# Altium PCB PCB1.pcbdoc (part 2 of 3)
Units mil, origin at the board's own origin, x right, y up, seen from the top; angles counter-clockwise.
Board outline 3855 x 3785 mil, 2 copper layers (Top Layer, Bottom Layer); 109 components, 98 nets, 407 pads, 573 vias.

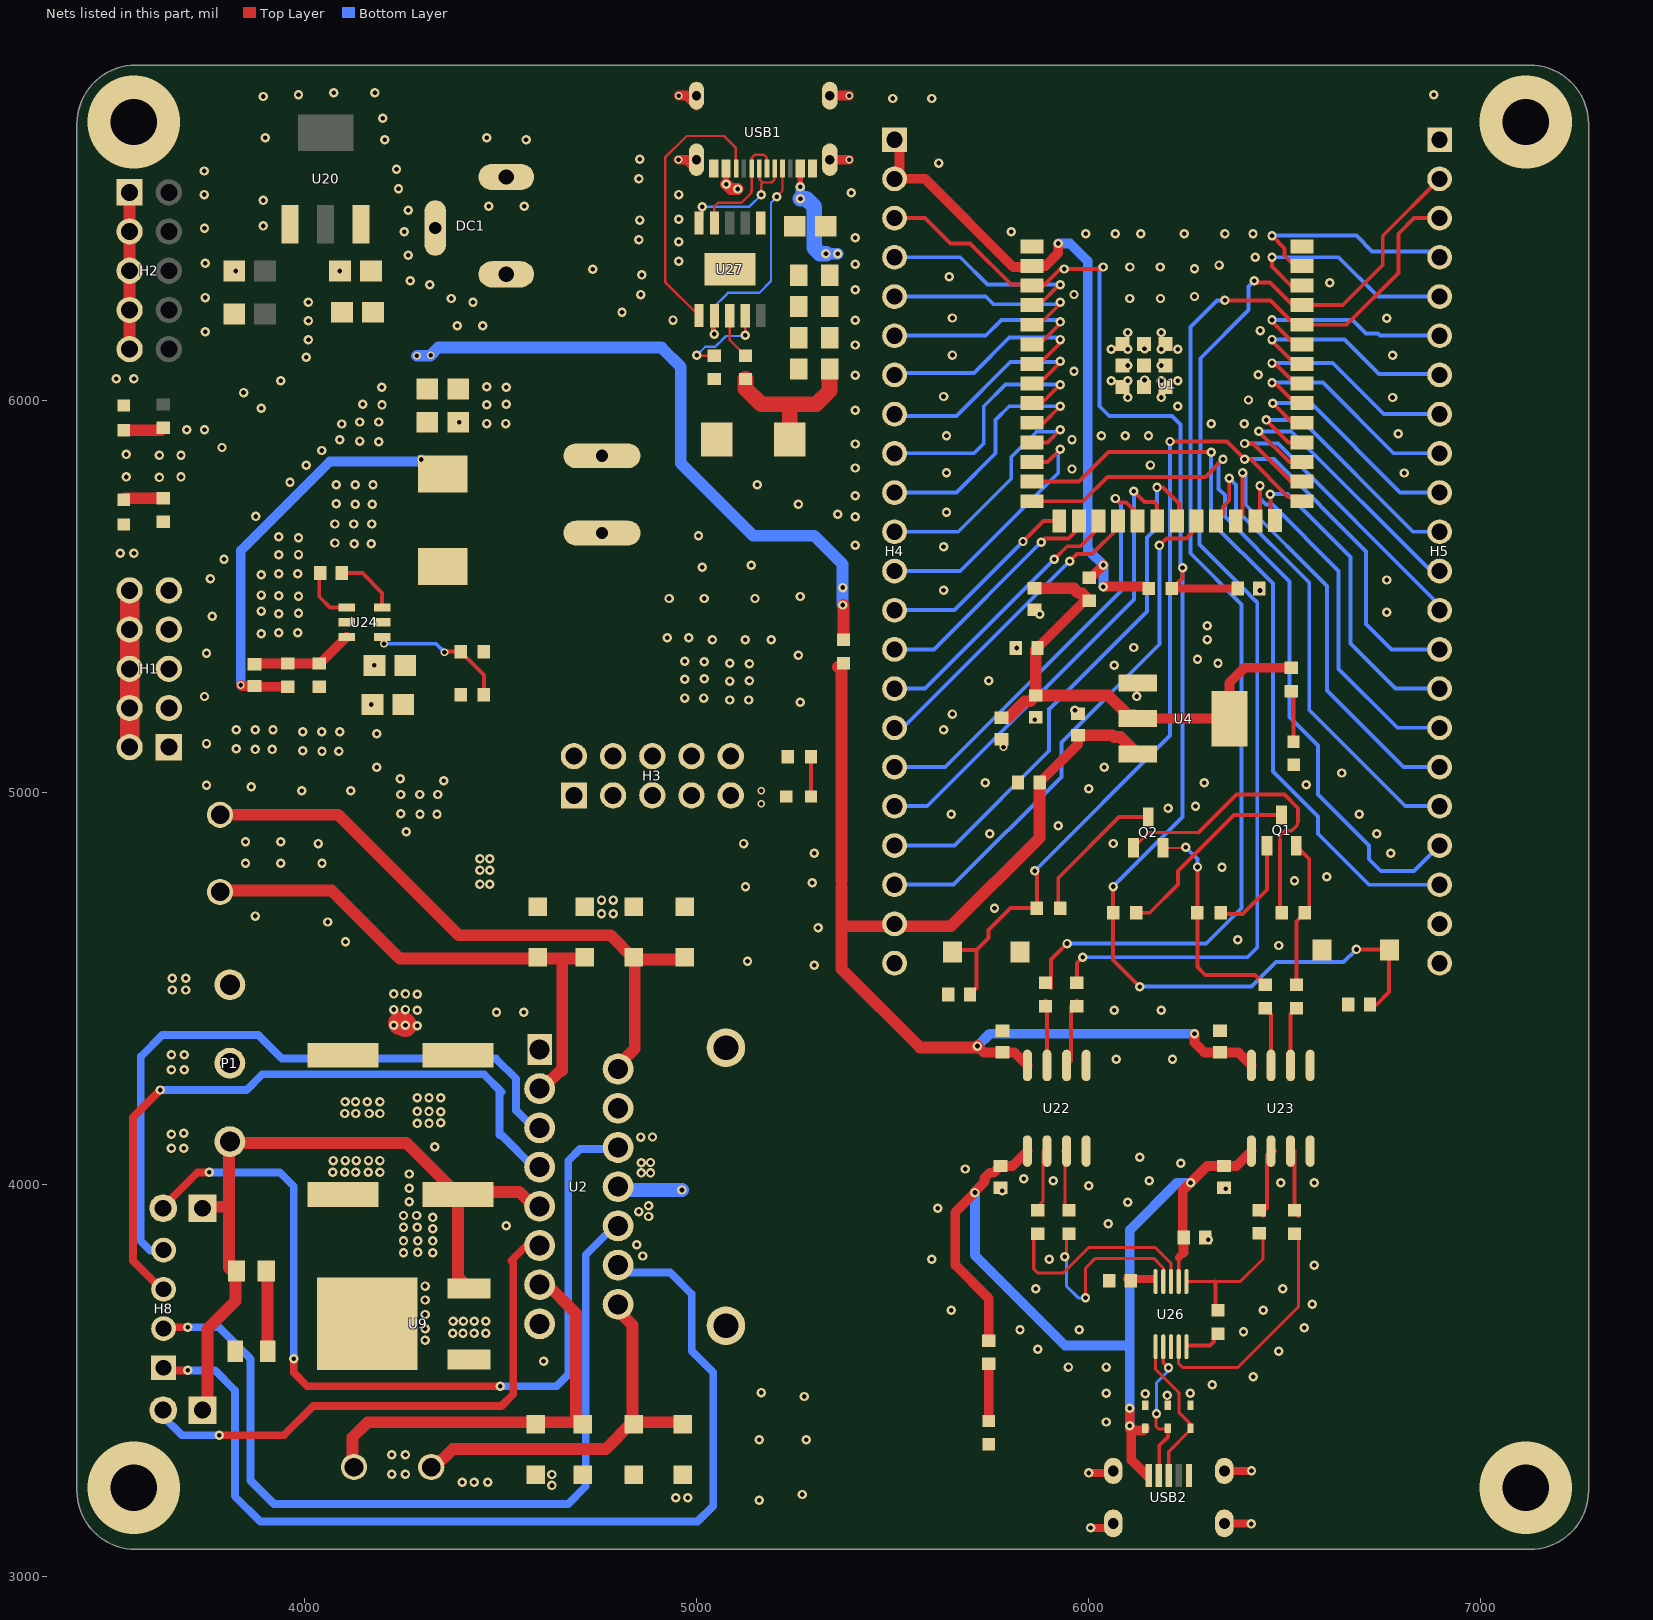
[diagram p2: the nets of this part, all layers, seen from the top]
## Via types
v1: diameter 24, hole 11.81, Top Layer to Bottom Layer, 257 vias
v2: diameter 24.02, hole 12.01, Top Layer to Bottom Layer, 174 vias
v3: diameter 24, hole 12, Top Layer to Bottom Layer, 122 vias
v4: diameter 19.68, hole 11.81, Top Layer to Bottom Layer, 16 vias
v5: diameter 236.22, hole 118.11, Top Layer to Bottom Layer, 4 vias

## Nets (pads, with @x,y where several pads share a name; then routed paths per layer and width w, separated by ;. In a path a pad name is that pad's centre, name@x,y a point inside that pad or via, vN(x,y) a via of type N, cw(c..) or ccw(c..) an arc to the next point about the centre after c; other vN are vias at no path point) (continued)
12V: C3.1 C18.2 C26.2 D1.1 D3.1 D4.1 D9.1 H3.2 H3.4 H3.6 H3.8 H3.10 P1.3 R8C1.2 R16.2 SW1C1.1 U2.4 U9.1 U24.5 | length 17.1
  Top Layer w60: 4242.77,4411.58 4252.77,4411.58 v2(4257.77,4406.58)
  other v2: 4432.77,3620.93 4378.76,3621.58 4404.54,3621.58 4462.77,3621.58 4379.3,3651.58 4405.62,3651.58 4433.01,3651.58 4462.77,3651.58 4287.77,4156.25 4317.77,4156.25 4347.77,4157.86 4347.77,4186.33 4287.77,4186.87 4317.77,4186.87 4287.77,4221.58 4317.77,4221.58 4347.77,4221.58 4288.13,4405.51 4227.77,4406.58 4288.13,4445.26 4227.77,4446.58 4257.77,4446.58 4288.13,4485.68 4227.77,4486.58 4257.77,4486.58 4447.77,4766.58 4472.77,4766.58 4447.77,4801.58 4472.77,4801.58 4447.77,4831.58 4472.77,4831.58
  other v3: 4402.77,3240.93 4432.77,3240.93 4467.77,3240.93
$1N34: D2C.2 R7C.2 | length 102.8
  Top Layer w30: D2C.2@3539.24,5746.49 3543.13,5750.39 R7C.2@3640.45,5750.39
$1N35: D3C.2 R8C.1 | length 94.8
  Top Layer w30: D3C.2@3539.51,5924.25 R8C.1@3634.34,5924.25
$1N5073: C17.2 L1.1 U24.6 | length 160.9
  Top Layer w10: C17.2@4095.59,5559.45 4148.03,5559.45 4198.27,5509.21 U24.6@4198.27,5471.85
$1N5109: C17.1 U24.1 | length 142.2
  Top Layer w10: C17.1@4040.47,5559.45 4038.03,5557.01 4038.03,5499.45 4065.63,5471.85 U24.1@4107.79,5471.85
$1N5190: R16.1 R17.2 U24.4 | length 358.9
  Top Layer w10: U24.4@4198.27,5397.05 4203.03,5392.29 v4(4203.03,5379.45) ; v4(4357.38,5358.11) 4358.72,5359.45 R17.2@4398.37,5359.45 4457.69,5300.13 R16.1@4457.69,5249.45
  Bottom Layer w10: v4(4203.03,5379.45) 4336.03,5379.45 v4(4357.38,5358.11)
$1N5474: C21.2 R18.2 R19.2 U24.3 | length 263.8
  Top Layer w25: C21.2@3873.03,5327.01 3875.13,5329.11 R18.2@3958.03,5329.11 R19.2@4038.03,5329.11 4039.85,5329.11 U24.3@4107.79,5397.05
$1N7060: R3.1 U27.9 | length 239.3
  Top Layer w6: v3(5000.89,6115.57) 5002.53,6113.93 R3.1@5045.01,6113.93 ; v3(5124.38,6166.33) U27.9@5124.38,6216.16
  Bottom Layer w6: v3(5000.89,6115.57) 5022.09,6136.77 5047.51,6136.77 5055.01,6144.27 5055.37,6144.27 5070.01,6158.92 5070.01,6159.27 5075.01,6164.27 5122.32,6164.27 v3(5124.38,6166.33)
$1N7101: R2.1 U27.8 | length 118.8
  Top Layer w6: U27.8@5085.01,6216.16 5085.01,6153.93 R2.1@5125.01,6113.93
$1N7262: C1.2 R5.2 R6.2 R7.2 R20.2 U27.1
$1N10307: D3C1.2 R8C1.1 | length 96.3
  Top Layer w10: D3C1.2@5292,4995.22 R8C1.1@5292,5091.53
$3N78: Q1.1 R10A.2 | length 256.9
  Top Layer w10: R10A.2@6336.64,4693.54 6339.95,4690.24 6392.58,4690.24 6454.58,4752.23 Q1.1@6454.58,4864.17
$3N79: Q2.1 R12A.2 | length 789.4
  Top Layer w8: Q2.1@6114.58,4859.17 6153.71,4898.31 6280.65,4898.31 ; 6487.58,4878.92 6487.58,4890.24 6500.13,4902.78 6517.58,4902.78 6533.01,4918.21 6533.01,4925.24 6533.9,4925.24 6534.42,4925.76
  Top Layer w10: 6280.65,4898.31 6377.58,4995.24 6499.26,4995.24 6534.42,4960.07 6534.42,4925.76 ; 6487.58,4878.92 6487.58,4698.28 R12A.2@6492.32,4693.54
$3N94: LED1.2 R11A.2 | length 129.4
  Top Layer w10: R11A.2@6516.98,5258.88 6522.44,5253.42 LED1.2@6522.44,5131.71
$3N145: Q2.3 R13.1 | length 373
  Top Layer w10: R13.1@5927.24,4705.24 5922.58,4709.9 5922.58,4782.58 6077.91,4937.91 Q2.3@6151.98,4937.91
$3N147: Q1.3 R8.1 | length 494.1
  Top Layer w10: R8.1@6121.64,4693.54 6155.89,4693.54 6227.58,4765.24 6227.58,4800.24 6370.26,4942.91 Q1.3@6491.98,4942.91
$3N10374: R25.1 U22.6 | length 177
  Top Layer w10: U22.6@5943.8,4304.15 5955,4315.35 5955,4455.34 R25.1@5970,4470.34
$3N10376: R7A1.1 U22.7 | length 167.8
  Top Layer w10: R7A1.1@5890,4470.34 5893.8,4466.54 U22.7@5893.8,4304.15
$3N10605: LED3.2 R2B1.1 | length 143.9
  Top Layer w25: LED3.2@5745.19,3399.29 5745.33,3399.42 R2B1.1@5745.33,3543.15
$3N10884: C16.2 U26.10 | length 66.1
  Top Layer w20: C16.2@6097.56,3760 6163.7,3760
$3N11013: R24.2 U22.3 | length 153.8
  Top Layer w8: U22.3@5933.8,4085.85 5940,4079.65 R24.2@5940,3934.66
$3N11016: R24.1 U26.9 | length 535.9
  Top Layer w8: v3(5939.36,3816.13) 5943.34,3820.11 R24.1@5943.34,3883.68 ; v3(5992.04,3711.39) 5992.04,3787.04 6017.27,3812.27 6165.75,3812.27 6190.49,3787.53 6190.49,3753.24 U26.9@6190.32,3753.07
  Bottom Layer w8: v3(5939.36,3816.13) 5943.56,3811.92 5943.56,3741.44 5973.61,3711.39 v3(5992.04,3711.39)
$3N11079: R22.2 U22.2 | length 161
  Top Layer w8: R22.2@5860,3934.66 5883.8,3958.46 U22.2@5883.8,4085.85
$3N11082: R22.1 U26.8 | length 534.9
  Top Layer w8: R22.1@5860,3875.34 5860,3785 5870,3775 5935,3775 6000,3840 6170,3840 6210,3800 U26.8@6210,3753.07
$3N11238: R26.1 U23.7 | length 152.4
  Top Layer w10: R26.1@6450,4450.34 6465,4435.34 U23.7@6465,4304.15
$3N11271: R27.1 U23.6 | length 152.4
  Top Layer w10: U23.6@6515,4304.15 6515,4435.34 R27.1@6530,4450.34
$3N11307: R28.2 U23.2 | length 184.3
  Top Layer w10: R28.2@6444.66,3920 6444.66,3930 6455,3940.34 6455,4075.85 U23.2@6465,4085.85 U23.2@6475,4085.85
$3N11312: R4.2 R28.1 U26.6 | length 343.9
  Top Layer w8: U26.6@6249.37,3753.07 6323.15,3753.07 6387.05,3753.07 6444.66,3810.68 R28.1@6444.66,3860.68
  Top Layer w10: R4.2@6320,3679.66 6323.15,3682.81 6323.15,3753.07
$3N11345: R29.2 U23.3 | length 170.3
  Top Layer w10: U23.3@6525,4085.85 6525,3929.66 R29.2@6535,3919.66
$3N11350: R29.1 U26.4 | length 588.5
  Top Layer w8: U26.4@6229.69,3586.93 6229.51,3586.75 6229.51,3543.99 6239.34,3534.16 6380.84,3534.16 6535,3688.31 R29.1@6535,3860.34
$3N15257: R4.1 U26.5 | length 95.9
  Top Layer w10: U26.5@6250.2,3586.1 6254.1,3590 6310,3590 6320,3600 R4.1@6320,3620.34
$5N2079: LED2.1 R1.1 | length 197.2
  Top Layer w30: R1.1@3900.81,3771.58 3906.07,3766.32 LED2.1@3906.07,3576.58
$5N2106: D4.2 D8.1 U2.14 U10.2 | length 1003.5
  Top Layer w30: U10.2@4323.52,3281.58 4334.17,3281.58 4378.52,3325.93 4768.36,3325.93 D4.2@4836.66,3394.23 ; U2.14@4787.77,3691.58 4836.66,3642.69 D4.2@4836.66,3394.23 ; D8.1@4962.77,3394.23 D4.2@4836.66,3394.23
$5N2107: D3.2 D7.1 U2.13 U10.1 | length 1087.1
  Top Layer w30: U10.1@4126.67,3281.58 4122.77,3285.48 4122.77,3355.93 4161.07,3394.23 D3.2@4709.07,3394.23 ; U2.13@4600,3745 4620,3745 4692.5,3672.5 4692.5,3410.8 D3.2@4709.07,3394.23 ; D3.2@4710,3393.3 D3.2@4709.07,3394.23
$5N2113: D6.1 D9.2 U2.3 U3.2 | length 1371.9
  Top Layer w30: U3.2@3785,4746.58 3788.43,4750 4070,4750 4243.3,4576.7 D6.1@4715,4576.7 ; U2.3@4587.77,4241.58 4603.42,4241.58 4652.77,4290.93 ; 4652.77,4574.07 4652.88,4574.18 ; 4657.77,4290.93 4657.77,4574.07
$5N2114: D1.2 D5.1 U2.2 U3.1 | length 1641.1
  Top Layer w30: U3.1@3785,4943.43 4086.67,4943.43 4394.17,4635.93 4781.02,4635.93 D5.1@4842.77,4574.18 ; U2.2@4787.77,4291.58 4842.77,4346.58 D5.1@4842.77,4574.18 ; D1.2@4967.77,4574.18 D5.1@4842.77,4574.18
+5V: C2.1 H6.1 H7.1 P1.1 R1.2 U2.9 U9.3 | length 1903.7
  Top Layer w30: H6.1@3737.77,3421.58 3752.77,3436.58 3752.77,3631.58 3824.73,3703.54 3824.73,3771.58 3807.77,3788.54 3807.77,3943.61 ; H7.1@3737.77,3941.58 3739.8,3943.61 3807.77,3943.61 ; C2.1@4391.6,3975 4391.6,3765.37 U9.3@4421.81,3735.16 ; U2.9@4587.77,3941.58 4547.77,3981.58 4394.37,3981.58 4389.37,3976.58 4259.37,4106.58 3807.77,4106.58 3807.77,3943.61
CC1: U27.7 USB1.A5 | length 592.3
  Top Layer w5: v3(5205.01,6519.27) 5219.22,6533.48 USB1.A5@5219.22,6591.26
  Top Layer w10: v3(5045.01,6169.27) 5045.01,6215.53 U27.7@5045.64,6216.16
  Bottom Layer w6: v3(5045.01,6169.27) 5040.01,6174.27 5040.01,6234.27 5080.01,6274.27 5160.01,6274.27 5190.01,6304.27 5190.01,6504.27 v3(5205.01,6519.27)
CC2: U27.6 USB1.B5 | length 707.9
  Top Layer w6: U27.6@5006.27,6216.17 4920.01,6302.42 4920.01,6619.27 4975.01,6674.27 5070.01,6674.27 5100.53,6643.76 5100.53,6591.26 USB1.B5@5101.11,6591.26
CHIP_PU: C6A.2 C14A.2 H4.3 R5A.1 R8.2 SW2.2 U1.3 | length 3797.2
  Top Layer w10: H4.3@5517.49,6465.24 5582.58,6465.24 5647.58,6400.24 5697.58,6400.24 5802.58,6295.24 5853.26,6295.24 5860.85,6287.65 5879.99,6287.65 5927.58,6335.24 v2(5937.58,6335.24) 6032.58,6335.24 v2(6037.58,6340.24) ; v2(6062.58,4760.24) 6062.32,4759.97 R8.2@6062.32,4693.54 6062.32,4572.68 v2(6130,4505) ; R5A.1@6212.24,5520.24 6239.59,5547.58 v2(6239.59,5573.04) ; v3(6682.83,4600) 6767.85,4600 SW2.2@6772.03,4604.18 ; 6734.67,4459.67 6766.13,4491.13 SW2.2@6766.13,4598.92 ; SW2.2@6772.03,4598.92 SW2.2@6772.03,4604.18 ; SW2.2@6775.42,4600.8 SW2.2@6772.03,4604.18
  Top Layer w20: R5A.1@6212.24,5520.24 C6A.2@6368.21,5520.24
  Bottom Layer w10: v2@6027.58,6340.24 6027.58,5985.24 6052.58,5960.24 6212.58,5960.24 6234.59,5938.23 v2@6234.59,5573.04 ; v2(6062.58,4760.24) 6239.59,4937.24 v2(6239.59,5573.04) ; v2(6130,4505) 6415,4505 6477.5,4567.5 6650.33,4567.5 v3(6682.83,4600)
DTR: Q2.2 R10A.1 R26.2 | length 567.9
  Top Layer w5: Q2.2@6189.38,4859.17 6246.52,4859.17 v2(6247.58,4860.24)
  Top Layer w10: v2(6277.58,4810.24) 6277.58,4693.81 R10A.1@6277.32,4693.54 6277.32,4555 6297.32,4535 6424.66,4535 R26.2@6450,4509.66
  Bottom Layer w10: v2(6247.58,4860.24) 6277.58,4830.24 v2(6277.58,4810.24)
EA: H7.2 U2.6 | length 2261.7
  Top Layer w20: H7.2@3637.77,3941.58 3727.77,4031.58 v2(3757.77,4031.58) ; v3(3972.77,3555.93) 3972.77,3520.93 4007.77,3485.93 v3(4499.73,3485.93)
  Bottom Layer w20: v2(3757.77,4031.58) 3937.12,4031.58 3972.77,3995.93 v3(3972.77,3555.93) ; v3(4499.73,3485.93) 4642.77,3485.93 4672.77,3515.93 4672.77,4060.93 4702.77,4090.93 4787.12,4090.93 U2.6@4787.77,4091.58
EB: H6.2 U2.11 | length 1379.6
  Top Layer w20: v3(3782.77,3360.93) 3947.77,3360.93 4022.77,3435.93 4497.77,3435.93 ; 4502.77,3435.93 4532.77,3465.93 4532.77,3805.93 ; 4527.77,3805.93 4563.42,3841.58 U2.11@4587.77,3841.58
  Bottom Layer w20: H6.2@3637.77,3421.58 3637.77,3410.93 3687.77,3360.93 v3(3782.77,3360.93)
ESP_3V3: H4.1 H4.2 R5A.2 R24A.2 U1.2 | length 1742.1
  Top Layer w25: H4.1@5517.49,6665.24 5517.49,6565.24 5582.58,6565.24 5807.58,6340.24 5852.74,6340.24 U1.2@5855.55,6343 5890.07,6343 5922.58,6375.5 v2(5922.58,6400.24) ; R24A.2@6001.98,5548.2 6005.55,5548.2 v2(6037.58,5580.24) ; v2(6037.58,5525.24) 6147.92,5525.24 R5A.2@6152.92,5520.24
  Bottom Layer w25: v2(5922.58,6400.24) 5952.58,6400.24 5997.58,6355.24 5997.58,5615.24 ; 6002.58,5615.24 v2(6037.58,5580.24) v2(6037.58,5525.24)
GND: C1.1 C1A.1 C2.2 C2A.1 C3.2 C6A.1 C7A.1 C7C.1 C8A.1 C8C.1 C9A.1 C9C.1 C10A.1 C10C.1 C13A.1 C14A.1 C18.1 C19.1 C20.1 C23.1 C24.2 C26.1 D2C.1 D3C1.1 D3C.1 D5.2 D6.2 D7.2 D8.2 DC1.2 DC1.3 H1.2 H1.4 H1.6 H1.8 H1.10 H2.1 H2.3 H2.5 H2.7 H2.9 H3.1 H3.3 H3.5 H3.7 H3.9 H4.22 H5.1 H5.21 H5.22 LED1.1 LED2.2 P1.2 R3.2 R17.1 R19.1 SW1.1 SW2.1 U1.1 U1.40 U1.41 U2.1 U2.8 U2.15 U4.1 U9.2 U11.1 U11.2 U20.1 U22.5 U23.5 U24.2 U27.11 USB1.1 USB1.2 USB1.3 USB1.4 USB1.A1B12 USB1.B1A12 | length 1187.6
  Top Layer w25: v4(4954.1,6613.9) 4974.93,6613.9 USB1.2@4999.93,6588.9 ; v4(4954.74,6777.28) 4974.93,6777.28 USB1.4@4999.93,6752.28 ; USB1.1@5340.09,6613.9 5389.34,6613.9 v4(5389.46,6613.78) ; USB1.3@5340.09,6777.28 v4(5389.46,6777.28)
  Top Layer w30: H2.9@3554.37,6130.73 H2.7@3554.37,6230.73 H2.5@3554.37,6330.73 H2.3@3554.37,6430.73 H2.1@3554.37,6530.73
  Top Layer w50: H1.2@3554.37,5115.73 H1.4@3554.37,5215.73 H1.6@3554.37,5315.73 H1.8@3554.37,5415.73 H1.10@3554.37,5515.73
  Bottom Layer w35: U2.8@4787.77,3991.58 4792.77,3986.58 v2(4962.77,3986.58)
  other v1: 5160,3195 5270,3210 5160,3350 5280,3350 5275,3460 5165,3470 4610,3550 4515,3895 6070,4320 6213.83,4320 4490,4440 4559.84,4440 6065,4445 6184.91,4445 5300,4560 5130,4570 6485,4610 4105,4620 6380,4625 5310,4655 4060,4670 5760,4705 5125,4760 5295,4770 6525,4775 6340,4810 3850,4820 3940,4820 4045,4820 5300,4845 6770,4845 4035,4870 5120,4870 3850,4875 3940,4875 6735,4895 4260,4900 4295,4945 4338.22,4945 5650,4945 6690,4945 4246.04,4946.44 4246.04,4995 4294.4,4995 4340,4995 3993.58,5005 4118.25,5005 6000,5010 3865,5015 6555,5020 5735.96,5025.24 4355,5030 4245,5035 6645,5050 4185,5064.7 6040,5065 4045,5105 4088.22,5105 3996.04,5106.44 3875,5110 3918.22,5110 3826.04,5111.44 4185,5150 3996.04,5155 4044.4,5155 4090,5155 3826.04,5160 3874.4,5160 3920,5160 4170.61,5224.45 5265,5230 5085,5236.04 5133.56,5236.04 4970,5241.04 5018.56,5241.04 5085,5284.4 5135,5285 5745,5285 4970,5289.4 5020,5290 4178.66,5324.45 5135,5328.22 5085,5330 5020,5333.22 4970,5335 5260,5350 5816.31,5368.54 5040.66,5390 5124.53,5390 5190.27,5390 4925,5395 4980,5395 3890,5405 3935,5408.02 3983.56,5408.02 3765,5450 3935,5456.38 3985,5456.98 6760,5460 3890,5462.91 4930,5495 5020,5495 5149.12,5495 3985,5500.2 5265,5500 3935,5501.98 3890,5503.71 5630,5515.55 6760,5542.08 3890,5555.09 3935,5558.02 3983.56,5558.02 5015,5575 5140,5580 3795,5595 3935,5606.38 3985,5606.98 5630,5626.62 5405,5630.4 4126.98,5635 4170.2,5635 4078.02,5636.44 3985,5650.2 3935,5651.98 5005,5655 4078.02,5685 4126.38,5685 4171.98,5685 5405,5702.94 3875.82,5704.18 5360,5710 4130,5735 4173.22,5735 5260,5735 4081.04,5736.44 5405,5757.34 4081.04,5785 4129.4,5785 4175,5785 5155,5785 3963.32,5791.68 6805,5815 5405,5827.61 4005,5835 4044.65,5872.39 3790,5880 5405,5888.82 4190,5895 4141.04,5896.44 4090,5900 6790,5915 4095,5940 4465,5941.04 4513.56,5941.04 4395.45,5944.45 4141.04,5945 4189.4,5945 5405,5974.96 3890,5980 4197.92,5988.5 4465,5989.4 4148.96,5989.94 4515,5990 6775,6007.45 5630,6010 4515,6033.22 4197.31,6033.5 4465,6035 3520,6055 5405,6064.29 6775,6115 5405,6141.37 4390,6190 4455,6190 4940,6205 5405,6204.84 6760,6210 4810,6225 4430,6250 4375,6260 6105,6260 6183.32,6260 6270,6265 4858.22,6270 5405,6281.91 4320,6295 6615,6300 4270,6305 5645,6315 4860,6320 4735,6335 6270,6336.13 5405,6347.65 4955,6354.59 4265,6370 4955,6405 4853.22,6410 5405,6415 4255,6430 4855,6460 4955,6461.88 4265,6485 3745,6525 4955,6525 5395,6530 4240,6540 4853.22,6565 3745,6584.98 4235,6590 4855,6615 4205,6665 3900,6670 4200,6720 5500,6770 5600,6770 3895,6775 3985,6780 6880,6780 4075,6785 4180,6785
  other v2: 4222.77,3261.58 4257.77,3261.58 4222.77,3311.58 4257.77,3311.58 4307.77,3603.28 4307.77,3633.07 4307.77,3669.1 4307.77,3706.05 4307.77,3741.58 4862.77,3818.27 4252.77,3826.58 4289.15,3827.4 4327.77,3826.68 4847.77,3846.58 4252.77,3856.58 4289.15,3856.58 4327.77,3856.58 4327.38,3888.07 4252.77,3891.58 4287.77,3891.58 4327.77,3916.58 4877.77,3918.91 4252.77,3921.58 4286.23,3921.58 4852.77,3931.58 4877.77,3946.58 4267.77,3956.58 4267.77,3990.84 4267.77,4027.31 4858.98,4030.02 4882.77,4030.02 4072.54,4031.58 4103.16,4031.58 4130.55,4031.58 4162.78,4031.58 4192.77,4031.58 4858.98,4056.27 4882.77,4056.58 4073.44,4061.58 4104.59,4061.58 4132.52,4061.58 4163.67,4061.58 4192.77,4061.58 3661.02,4092.94 3692.77,4092.94 4332.77,4096.58 4857.77,4121.58 4887.75,4121.75 3661.02,4129.04 3692.77,4131.58 4102.98,4181.58 4131.17,4181.58 4165.02,4181.58 4192.77,4181.58 4103.79,4211.58 4130.37,4211.58 4160.18,4211.58 4192.77,4211.58 3661.02,4293.12 3693.84,4293.12 3661.02,4331.41 3693.84,4331.58 3662.77,4496.58 3697.77,4496.58 3662.77,4526.58 3697.77,4526.58 3875,4685 3750.45,5018.47 3750.45,5125.02 3745.45,5245.02 3750.45,5355.02 6302.58,5390.24 6302.58,5425.24 3760.45,5545.02 5637.58,5715.24 3630.45,5803.6 3545.45,5805.02 5637.58,5815.24 6157.58,5835.24 3630.45,5860.02 3545.45,5862.3 5637.58,5910.24 3940,6050 5652.58,6115.76 4010.45,6155.02 5652.58,6210.24 5802.58,6430.24 3745.45,6438.76 5617.58,6605.24
  other v3: 4947.07,3201.58 4977.51,3201.58 4631.37,3233.13 4631.37,3261.03 4757.77,4690.93 4787.77,4690.93 4757.77,4725.93 4787.77,4725.93 6607.58,4785.24 6062.58,4870.24 5747.58,4895.24 5922.58,4915.24 6202.58,4960.24 6272.58,4965.24 6295,5025 5630,5160 5652.58,5200.24 5965,5210 6122.58,5245.24 6065,5325 6330,5330 6277.58,5340.24 6115,5370 5875,5455 6436.95,5515.24 3530.45,5610.02 3565.45,5610.02 3685.45,5805.02 5957.58,5825.24 3685.45,5860.02 5957.58,5900.24 6032.58,5910.24 6093.39,5910.24 6152.58,5910.24 3700.45,5925.02 3745.45,5925.02 6312.58,5940.24 6396.78,5940.24 6227.58,5985.24 6407.58,6001.22 6100.08,6007.67 6185.08,6007.67 3845,6020 6057.58,6050.24 6100.08,6050.24 6185.08,6050.24 6227.58,6050.24 6142.58,6052.01 3565.45,6055.02 6432.58,6065.24 5962.58,6074.22 6100.08,6089.05 6185.08,6089.05 4005,6110 6057.58,6130.24 6100.08,6130.24 6185.08,6130.24 6227.58,6130.24 6142.58,6132.01 6100.08,6173.17 6185.08,6173.17 3747.46,6175.02 6437.94,6178.17 4010.45,6203.52 4010.45,6250.02 3747.46,6262.26 5962.58,6270.24 6105.32,6340.24 6182.58,6340.24 6332.58,6345.24 3747.46,6349.5 6424.69,6365.24 5992.58,6425.24 6067.58,6425.24 6132.58,6425.24 6243.84,6425.24 6347.58,6425.24 6419.13,6425.24 3895.45,6445.02 4470.45,6495.02 4560.45,6495.02 3895.45,6510.02 4565.45,6665.02 4465.45,6670.02
  other v4: 5165.45,4971.74 5165.45,5005.02 5782.98,5115.98 5862.58,5185.98 3825,6330 4090,6330
  other v5: 3565,3227.48 3565,6710 7115,6710
GND1: C4.1 C16.1 C22.1 C25.2 D2A.1 D3A.1 D4A.1 LED3.1 U22.4 U23.4 U26.3 USB2.5 USB2.6 | length 265.8
  Top Layer w20: v3(6000,3265) 6057.43,3265 USB2.6@6062.66,3270.23 ; v3(6005,3125) 6051.28,3125 USB2.6@6062.66,3136.38 ; USB2.6@6346.13,3136.38 6413.62,3136.38 v3(6415,3135) ; USB2.6@6346.13,3270.23 v3(6415.31,3270.23)
  other v1: 6045,3468.62 6315,3490 6420,3510 5948.52,3535 6045,3535 6485,3575 5870,3580 6395,3625 5825,3630 5975.72,3630 6550,3635 5650,3680 6445,3680 6570,3695 5865,3735 6495,3735 6575,3795 5600,3810 5900,3810 6305,3860 6050,3900 5615,3940 6100,3955 5780,3985 6350,3990 6000,3997.54 6490,4005 6575,4005 5910,4010 6155,4010 5835,4015 5685,4040 6235,4055 6130,4070
  other v3: 6045,3395 6200.6,3462.63 6144.4,3467.17 6259.4,3468.14
  other v5: 7115,3227.48
GPIO0: C13A.2 H5.14 R13.2 SW1.2 U1.27 | length 2923.3
  Top Layer w10: SW1.2@5652.98,4593.31 5657.98,4598.31 5714.4,4598.31 ; C13A.2@5697.56,4485 5714.4,4501.84 5714.4,4598.31 ; v2(5862.58,4800.24) 5867.92,4794.9 R13.2@5867.92,4705.24 5800.24,4705.24 5745,4650 5745,4628.91 5714.4,4598.31 ; v2(6207.58,5895.24) 6352.58,5895.24 v2(6397.58,5850.24) 6412.58,5850.24 6507.58,5755.24 6532.24,5755.24 U1.27@6544.53,5743
  Bottom Layer w10: v2(5862.58,4800.24) 6207.58,5145.24 v2(6207.58,5895.24) ; v2(6397.58,5850.24) 6472.58,5850.24 6707.58,5615.24 6707.58,5430.24 6772.58,5365.24 H5.14@6882.58,5365.24
GPIO1: H5.4 U1.39 | length 570.2
  Top Layer w10: v2(6467.58,6420.24) 6499.95,6387.86 6499.95,6369.07 6525.68,6343.34 6544.14,6343.34 U1.39@6544.53,6343
  Bottom Layer w10: v2(6467.58,6420.24) 6682.58,6420.24 6722.82,6380 6880,6380 H5.4@6895,6365
GPIO2: H5.5 U1.38 | length 588.4
  Top Layer w10: v2(6467.58,6365.24) 6467.58,6360.24 6467.24,6359.89 6467.24,6341.78 6525.68,6283.34 6539.82,6283.34 6544.48,6288 U1.38@6544.53,6293
  Bottom Layer w10: v2(6467.58,6365.24) 6637.58,6365.24 6737.58,6265.24 H5.5@6882.58,6265.24
GPIO3: H4.13 U1.15 | length 501.7
  Top Layer w10: v2(5832.58,5640.24) 5884.95,5692.61 U1.15@5925.04,5692.61
  Bottom Layer w10: H4.13@5517.49,5465.24 5657.58,5465.24 v2(5832.58,5640.24)
GPIO4: H4.4 U1.4 | length 532.8
  Top Layer w10: U1.4@5855.55,6243 5873.96,6243 5926.2,6295.24 v2(5927.58,6295.24)
  Bottom Layer w10: H4.4@5517.49,6365.24 5672.58,6365.24 5742.58,6295.24 v2(5927.58,6295.24)
GPIO5: H4.5 U1.5 | length 518.4
  Top Layer w10: U1.5@5855.55,6193 5873.96,6193 5927.58,6246.62 v2(5927.58,6250.24)
  Bottom Layer w10: H4.5@5517.49,6265.24 5737.58,6265.24 5757.58,6245.24 5922.58,6245.24 v2(5927.58,6250.24)
GPIO6: H4.6 U1.6 | length 526.6
  Top Layer w10: U1.6@5855.55,6143 5873.96,6143 5927.58,6196.62 v2(5927.58,6200.24)
  Bottom Layer w10: H4.6@5517.49,6165.24 5737.58,6165.24 5777.58,6205.24 5922.58,6205.24 v2(5927.58,6200.24)
GPIO7: H4.7 U1.7 | length 550.3
  Top Layer w10: U1.7@5855.55,6093 5873.96,6093 5927.58,6146.62 v2(5927.58,6155.24)
  Bottom Layer w10: H4.7@5507.49,6070.24 5707.58,6070.24 5797.58,6160.24 v2@5917.58,6160.24
GPIO8: H4.12 U1.12 | length 656.2
  Top Layer w10: U1.12@5855.55,5843 5895.34,5843 v2(5927.58,5875.24)
  Bottom Layer w10: H4.12@5517.49,5565.24 5672.58,5565.24 5922.58,5815.24 5922.58,5870.24 v2(5927.58,5875.24)
GPIO9: H4.15 U1.17 | length 695.3
  Top Layer w10: v2(5912.58,5595.24) 5945.42,5628.08 5978.92,5628.08 6024.99,5674.15 U1.17@6025.04,5692.61
  Bottom Layer w10: H4.15@5517.49,5265.24 5582.58,5265.24 v2(5912.58,5595.24)
GPIO10: H4.16 U1.18 | length 786.8
  Top Layer w10: v2(5951.6,5589.85) 5969.83,5608.08 6008.92,5608.08 6074.99,5674.15 U1.18@6075.04,5692.61
  Bottom Layer w10: H4.16@5517.49,5165.24 5526.99,5165.24 v2(5951.6,5589.85)
GPIO11: H4.17 U1.19 | length 1087.9
  Top Layer w10: v2(6068.32,5749.99) 6078.08,5740.24 6095.82,5740.24 6129.2,5706.85 6124.99,5702.64 U1.19@6125.04,5692.61
  Bottom Layer w10: H4.17@5517.49,5065.24 5634.3,5065.24 6082.58,5513.52 6082.58,5735.73 v2(6068.32,5749.99)
GPIO12: H4.18 U1.20 | length 1206.8
  Top Layer w10: v2(6115.24,5768.23) 6142.24,5741.22 6167.4,5741.22 6174.99,5733.64 U1.20@6175.04,5692.61
  Bottom Layer w10: H4.18@5517.49,4965.24 5587.58,4965.24 6115.24,5492.89 v2(6115.24,5768.23)
GPIO13: H4.19 U1.21 | length 1388.8
  Top Layer w10: v2(6174.25,5778.23) 6189.25,5778.23 6229.99,5737.49 6229.99,5697.61 U1.21@6225.04,5692.61
  Bottom Layer w10: H4.19@5517.49,4865.24 5657.58,4865.24 5899.03,5106.68 5899.03,5211.68 ; 5899.03,5213.85 5899.03,5211.68 ; v2(6174.25,5778.23) 6174.25,5675.1 6149.25,5650.1 6149.25,5461.91 5899.03,5211.68
GPIO14: H4.20 U1.22 | length 1351.7
  Top Layer w10: v2(6180.57,5630.24) 6198.42,5648.08 6248.92,5648.08 6274.99,5674.15 U1.22@6275.04,5692.61
  Bottom Layer w10: H4.20@5517.49,4765.24 5655.76,4765.24 5930.51,5039.98 5930.51,5128.16 6180.57,5378.23 v2(6180.57,5630.24)
GPIO15: H4.8 U1.8 | length 566
  Top Layer w10: U1.8@5855.55,6043 5873.96,6043 5927.58,6096.62 v2(5927.58,6100.24)
  Bottom Layer w10: H4.8@5517.49,5960.24 5662.58,5960.24 5800.08,6097.74 5925.08,6097.74 v2@5927.58,6095.24
GPIO16: H4.9 U1.9 | length 629.9
  Top Layer w10: U1.9@5855.55,5993 5880.34,5993 v2(5927.58,6040.24)
  Bottom Layer w10: H4.9@5517.49,5865.24 5707.58,5865.24 5732.58,5890.24 5732.58,5985.24 5787.58,6040.24 v2(5927.58,6040.24)
GPIO17: H4.10 U1.10 | length 640.6
  Top Layer w10: U1.10@5855.55,5943 5885.34,5943 v2(5927.58,5985.24)
  Bottom Layer w10: H4.10@5517.49,5765.24 5662.58,5765.24 5762.58,5865.24 5762.58,5950.24 5797.58,5985.24 v2(5927.58,5985.24)
GPIO18: H4.11 U1.11 | length 635.4
  Top Layer w10: U1.11@5855.55,5893 5895.34,5893 v2(5927.58,5925.24)
  Bottom Layer w10: H4.11@5517.49,5665.24 5667.58,5665.24 5802.58,5800.24 5802.58,5855.24 5867.58,5920.24 5922.58,5920.24 v2(5927.58,5925.24)
GPIO19: H5.20 U1.13 | length 1938.1
  Top Layer w10: U1.13@5855.55,5793 5975.34,5793 6050.57,5868.23 v2(6312.54,5868.23)
  Bottom Layer w10: v2(6312.54,5868.23) 6312.54,5690.28 6470.08,5532.74 6470.08,5053.5 6585,4938.58 6585,4895 6715,4765 H5.20@6895,4765
GPIO20: H5.19 U1.14 | length 1934.5
  Top Layer w10: U1.14@5855.55,5743 5985.34,5743 6047.58,5805.24 6297.58,5805.24 v2(6342.58,5850.24)
  Bottom Layer w10: v2(6342.58,5850.24) 6331.56,5839.21 6331.56,5774.57 6347.58,5758.55 6347.58,5703.76 6512.58,5538.76 6512.58,5192.42 6585,5120 6585,4995 6715,4865 6715,4830 6745,4800 6830,4800 H5.19@6895,4865
GPIO21: H5.18 U1.23 | length 1220.7
  Top Layer w10: U1.23@6325.04,5692.61 6342.27,5709.89 6342.27,5728.35 6358.57,5744.64 v2(6358.57,5801.83)
  Bottom Layer w10: v2(6358.57,5801.83) 6375.57,5784.82 6375.57,5722.24 6562.58,5535.24 6562.58,5210.24 6807.58,4965.24 H5.18@6882.58,4965.24
GPIO35: H5.13 U1.28 | length 858
  Top Layer w10: v2@6392.58,5890.24 6419.39,5890.24 U1.28@6516.02,5793 ; U1.28@6526.02,5793 U1.28@6544.53,5793
  Bottom Layer w10: v2(6397.58,5890.24) 6482.58,5890.24 6882.58,5490.24 H5.13@6882.58,5465.24
GPIO36: H5.12 U1.29 | length 739.8
  Top Layer w10: v2(6433.53,5921.18) 6511.72,5843 U1.29@6544.53,5843
  Bottom Layer w10: v2(6433.53,5921.18) 6516.63,5921.18 6872.58,5565.24 H5.12@6882.58,5565.24
GPIO37: H5.11 U1.30 | length 663.7
  Top Layer w10: v2(6452.58,5950.24) 6509.82,5893 U1.30@6544.53,5893
  Bottom Layer w10: v2(6452.58,5950.24) 6542.58,5950.24 6827.58,5665.24 H5.11@6882.58,5665.24
GPIO38: H5.10 U1.31 | length 603.2
  Top Layer w10: v3(6469.48,5993) 6519.48,5943 U1.31@6544.53,5943
  Bottom Layer w10: v3(6469.48,5993) 6566.54,5993 6794.3,5765.24 H5.10@6882.58,5765.24
GPIO39: H5.9 U1.32 | length 588.1
  Top Layer w10: v2(6467.58,6045.24) 6473.78,6045.24 6526.02,5993 U1.32@6544.53,5993
  Bottom Layer w10: v2(6467.58,6045.24) 6597.58,6045.24 6777.58,5865.24 H5.9@6882.58,5865.24
GPIO40: H5.8 U1.33 | length 567.4
  Top Layer w10: v2(6467.58,6095.24) 6473.78,6095.24 6526.02,6043 U1.33@6544.53,6043
  Bottom Layer w10: v2(6467.58,6095.24) 6622.58,6095.24 6752.58,5965.24 H5.8@6882.58,5965.24
GPIO41: H5.7 U1.34 | length 557.2
  Top Layer w10: v2(6467.58,6155.24) 6467.58,6151.44 6526.02,6093 U1.34@6544.53,6093
  Bottom Layer w10: v2(6467.58,6155.24) 6652.58,6155.24 6740.08,6067.74 6880.08,6067.74 H5.7@6882.58,6065.24
GPIO42: H5.6 U1.35 | length 536.5
  Top Layer w10: v2(6467.58,6205.24) 6467.58,6201.44 6523.78,6145.24 6542.24,6145.24 U1.35@6544.53,6143
  Bottom Layer w10: v2(6467.58,6205.24) 6672.58,6205.24 6707.58,6170.24 6737.58,6170.24 6742.58,6165.24 H5.6@6882.58,6165.24
GPIO45: H5.15 U1.26 | length 825.5
  Top Layer w10: v2(6463.48,5761.14) 6463.48,5705.29 U1.26@6475.04,5693.79
  Bottom Layer w10: v2(6463.48,5761.14) 6506.68,5761.14 6667.58,5600.24 6667.58,5380.24 6782.58,5265.24 H5.15@6882.58,5265.24
GPIO46: H4.14 U1.16 | length 603.9
  Top Layer w10: v2(5879.2,5638.62) 5888.66,5648.08 5948.92,5648.08 5974.99,5674.15 U1.16@5975.04,5692.61
  Bottom Layer w10: H4.14@5517.49,5365.24 5605.81,5365.24 v2(5879.2,5638.62)
GPIO47: H5.17 U1.24 | length 1132.7
  Top Layer w10: U1.24@6375.04,5692.61 6392.27,5709.89 6392.27,5765.03 6392.58,5765.34 v2(6392.58,5815.24)
  Bottom Layer w10: v2(6392.58,5815.24) 6397.58,5815.24 6400.57,5812.24 6400.57,5734.05 6607.58,5527.04 6607.58,5260.24 6802.58,5065.24 H5.17@6882.58,5065.24
GPIO48: H5.16 U1.25 | length 962.7
  Top Layer w10: U1.25@6425.04,5692.61 6436.48,5704.09 6436.48,5772.32 6436.93,5772.78 v2(6436.93,5782.69)
  Bottom Layer w10: v2(6436.93,5782.69) 6436.93,5772.78 6436.48,5772.32 6436.48,5749.95 6452.3,5734.13 6468.69,5734.13 6637.58,5565.24 6637.58,5315.24 6787.58,5165.24 H5.16@6882.58,5165.24
IN1: H8.4 U2.5 | length 1709.8
  Bottom Layer w20: H8.4@3637.77,3831.58 3607.77,3831.58 3582.77,3856.58 3582.77,4326.58 3637.77,4381.58 3882.77,4381.58 3942.77,4321.58 4488.42,4321.58 4540,4270 4540,4189.35 U2.5@4587.77,4141.58
IN2: H8.3 U2.7 | length 1705.5
  Top Layer w20: v2(3632.77,4241.58) 3562.77,4171.58 3562.77,3806.58 H8.3@3637.77,3731.58
  Bottom Layer w20: v2(3632.77,4241.58) 3852.77,4241.58 3892.77,4281.58 4457.77,4281.58 4502.77,4236.58 ; 4497.77,4126.58 4497.77,4236.58 ; 4502.77,4126.58 U2.7@4587.77,4041.58
IN3: H8.2 U2.10 | length 2158.6
  Top Layer w20: H8.2@3637.77,3631.58 3642.77,3636.58 v2(3702.77,3636.58)
  Bottom Layer w20: v2(3702.77,3636.58) 3782.12,3636.58 3862.77,3555.93 3862.77,3245.93 3922.77,3185.93 4672.77,3185.93 4717.77,3230.93 4717.77,3821.58 U2.10@4787.77,3891.58
IN4: H8.1 U2.12 | length 2533.6
  Top Layer w20: H8.1@3637.77,3531.58 3642.77,3526.58 v2(3702.77,3526.58)
  Bottom Layer w20: v2(3702.77,3526.58) 3772.12,3526.58 3822.77,3475.93 3822.77,3205.93 3887.77,3140.93 5002.77,3140.93 5042.77,3180.93 5042.77,3520.93 4987.77,3575.93 4987.77,3720.93 4932.77,3775.93 4803.42,3775.93 U2.12@4787.77,3791.58
RTS: Q1.2 R12A.1 R27.2 | length 381.8
  Top Layer w10: Q1.2@6529.38,4864.17 6562.58,4830.97 6562.58,4704.49 R12A.1@6551.64,4693.54 6530,4671.9 R27.2@6530,4509.66
U0RXD: H5.3 R7A1.2 U1.36 | length 3009.7
  Top Layer w10: R7A1.2@5904.31,4501.22 5904.31,4574.31 v3(5945,4615) ; v2(6347.58,6255.24) 6463.78,6255.24 6516.02,6203 6534.48,6203 U1.36@6544.53,6193 ; U1.36@6544.53,6193 6658,6193 6790,6325 6790,6425 6830,6465 H5.3@6895,6465
  Bottom Layer w10: v3(5945,4615) 6300,4615 6390,4705 6390,5480 6259.59,5610.41 6259.59,6187.24 6327.58,6255.24 v2(6347.58,6255.24)
U0TXD: H5.2 R25.2 U1.37 | length 3007.3
  Top Layer w10: R25.2@5970,4529.66 5970,4565 v3(5985,4580) ; v2(6422.58,6305.24) 6427.58,6300.24 6462.58,6300.24 6519.82,6243 U1.37@6544.53,6243 6648,6243 6750,6345 6750,6420 H5.2@6895,6565
  Bottom Layer w10: v3(5985,4580) 6405,4580 6430,4605 6430,5485 6426.76,5488.24 6425.77,5488.24 6409.95,5504.05 6409.95,5505.05 6282.54,5632.46 6282.54,5866.51 6284,5867.98 6284,5873.64 6285,5874.64 6285,6107.65 6407.58,6230.24 6407.58,6290.24 v2(6422.58,6305.24)
USB_DN: D3A.2 U26.2 USB2.2 | length 385.8
  Top Layer w8: v3(6173.15,3415.79) 6173.15,3412.1 6171.84,3410.79 6171.84,3383.16 6178.06,3376.94 6200.05,3376.94 D3A.2@6201.9,3378.78 ; U26.2@6190.32,3586.93 6190.32,3546.41 v3(6203.69,3533.04)
  Top Layer w10: USB2.2@6178.8,3258.42 6180,3259.62 6180,3335 6201.9,3356.9 D3A.2@6201.9,3378.78
  Bottom Layer w8: v3(6173.15,3415.79) 6173.15,3495 6203.69,3525.54 v3(6203.69,3533.04)
USB_DP: D4A.2 U26.1 USB2.3 | length 388.1
  Top Layer w8: U26.1@6170.63,3586.93 6170.63,3529.37 6230,3470 6230,3420 6259.4,3390.6 D4A.2@6259.4,3378.78 ; USB2.3@6204.39,3258.42 6204.39,3319.39 D4A.2@6259.4,3374.4
  Top Layer w10: D4A.2@6259.4,3374.4 D4A.2@6259.4,3378.78
USBD+: U27.4 USB1.A6 USB1.B6 | length 296.2
  Top Layer w6: U27.4@5045.64,6452.39 5045.64,6494.9 5055.01,6504.27 5114.66,6504.27 5140.01,6529.63 5140.01,6534.63 5140.48,6535.1 USB1.B6@5140.48,6591.26 ; USB1.B6@5139.71,6609.27 5141.27,6610.83 5141.27,6619.28 5148.88,6626.9 5171.46,6626.9 5179.08,6619.28 5179.08,6592.03 USB1.A6@5179.85,6591.26
USBD-: U27.5 USB1.A7 USB1.B7 | length 341.6
  Top Layer w6: U27.5@5006.27,6452.39 5015.01,6461.13 v3(5015.01,6494.27) ; USB1.A7@5160.17,6591.26 5160.95,6590.49 5160.95,6563.24 5168.56,6555.62 ; v3(5165.01,6524.27) 5165.01,6552.07 5168.56,6555.62 ; USB1.B7@5199.54,6591.26 5198.76,6590.48 5198.76,6563.24 5191.14,6555.62 5168.56,6555.62
  Bottom Layer w6: v3(5015.01,6494.27) 5135.01,6494.27 v3(5165.01,6524.27)
VBUS: C4.2 C22.2 C25.1 D2A.2 R2B1.2 U22.1 U23.1 U26.7 USB2.1 | length 2646.2
  Top Layer w8: U26.7@6229.69,3753.07 6229.69,3814.69
  Top Layer w20: 6229.69,3814.69 6242.18,3827.18
  Top Layer w25: R2B1.2@5745.33,3602.47 5745.33,3709.67 5660,3795 5660,3930 v3(5710,3980) 5710,3982.56 5734.78,4007.35 5734.78,4017.51 5747.96,4030.69 5758.13,4030.69 C25.1@5775,4047.56 5805.51,4047.56 U22.1@5843.8,4085.85 ; v2(6105,3430) 6105,3377.33 6108.78,3373.54 ; D2A.2@6144.4,3378.78 6139.16,3373.54 6108.78,3373.54 ; USB2.1@6148.43,3258.42 6108.78,3298.07 6108.78,3373.54 ; C4.2@6240,3877.27 6240,3985 v3(6260,4005) 6302.56,4047.56 C22.2@6345,4047.56 6376.71,4047.56 U23.1@6415,4085.85 ; 6242.18,3827.18 C4.2@6242.18,3865.09
  Bottom Layer w25: v3(5710,3980) 5710,3820 5940,3590 6095,3590 6105,3580 ; v1(6105,3385.66) v2(6105,3430) 6105,3580 ; v3(6260,4005) 6225,4005 6105,3885 6105,3580
VBUS2: D2.2 R2.2 R5.1 R6.1 R7.1 R20.1 USB1.A4B9 USB1.B4A9 | length 781.9
  Top Layer w15: v3(5075.52,6551.07) USB1.B4A9@5075.52,6591.26 ; v3(5264.5,6545.09) USB1.A4B9@5264.5,6591.26
  Top Layer w30: v3(5075.52,6551.07) 5087.32,6539.27 v3(5105.01,6539.27)
  Top Layer w40: R2.2@5125.01,6054.61 5125.01,6029.99 5165,5990 5237.87,5990 5305,5990 5339.38,6024.38 R5.1@5339.38,6080.31 ; D2.2@5237.94,5900 5237.94,5989.93
  Bottom Layer w25: v3(5264.5,6545.09) 5264.5,6514.78 v3(5265.01,6514.27)
  Bottom Layer w30: v3(5330.01,6374.27) v3(5360.01,6374.27)
  Bottom Layer w40: v3(5265.01,6514.27) 5280.01,6514.27 5300.01,6494.27 5300.01,6389.27 5315.01,6374.27 v3(5330.01,6374.27)
VCC: C7C.2 C8C.2 C19.2 C20.2 C21.1 H1.1 H1.3 H1.5 H1.7 H1.9 L1.2 R7C.1 R14.1 R18.1 U20.3 | length 2680.6
  Top Layer w25: v4(3838.03,5274.45) 3840.59,5271.89 C21.1@3873.03,5271.89 3875.13,5269.79 R18.1@3958.03,5269.79
  Top Layer w30: R14.1@5375,5389.66 v1@5375,5478.43
  Bottom Layer w25: v4(3838.03,5274.45) 3838.03,5617.59 4064.89,5844.45 4293.03,5844.45 v4(4298.03,5849.45)
  Bottom Layer w30: v4(4287.08,6114.24) 4320.87,6114.24 v4(4322.08,6115.45) 4341.63,6135 4910.45,6135 4960,6085.45 4960,5845 4960,5840 5145,5655 5300,5655 5372.5,5582.5 v1(5372.5,5522.83) v1(5372.5,5478.43)
VCC_3V3: C1A.2 C2A.2 C9A.2 C10A.2 R11A.1 R24A.1 U4.2 U4.4 | length 1352.3
  Top Layer w25: C2A.2@5869.54,5368.54 5989.88,5488.88 R24A.1@6001.98,5488.88 ; U4.2@6125.05,5188.54 U4.4@6358.91,5188.54 6358.91,5280.24 6396.87,5318.2 R11A.1@6516.98,5318.2
  Top Layer w30: C10A.2@5777.98,5191.1 5794.84,5191.1 5836.93,5233.19 5850.63,5233.19 C9A.2@5865,5247.56 ; C1A.2@5861.98,5521.1 5962.63,5521.1 ccw(c5984.97,5532.33) 5983.49,5507.37 R24A.1@6001.98,5488.88 ; C2A.2@5869.54,5368.54 5865,5364 C9A.2@5865,5247.56 ; U4.2@6125.05,5188.54 6115.36,5198.24 6099.69,5198.24 6050.36,5247.56 C9A.2@5865,5247.56
VCC_5V: C7A.2 C8A.2 C23.2 C24.1 H4.21 R14.2 U4.3 U22.8 U23.8 | length 3135.4
  Top Layer w25: v3@5720,4350 5732.56,4337.44 C24.1@5780,4337.44 5810.51,4337.44 U22.8@5843.8,4304.15 ; C7A.2@5875.14,5025.24 5973.18,5123.28 C8A.2@5973.18,5145.98 ; v3(6270,4385) 6270,4362.44 6295,4337.44 C23.2@6335,4337.44 6381.71,4337.44 U23.8@6415,4304.15
  Top Layer w30: R14.2@5360,5320.34 5370,5310.34 5370,4775 ; 5370.1,4760.24 5370.1,4658.9 ; v3(5716.4,4353.6) 5720,4350 5570,4350 5370.1,4549.9 5370.1,4658.9 ; 5875,5000 5875,4885 5648.9,4658.9 5370.1,4658.9 ; C8A.2@5973.18,5145.98 6061.39,5145.98 6065.48,5141.89 6081.15,5141.89 U4.3@6125.05,5097.99
  Bottom Layer w25: v3(5716.4,4353.6) 5747.8,4385 v3@6260,4385
VIN: D2.1 DC1.4 SW1C1.2
pads on no net: U27.2 U27.3 U27.10 USB1.A8 USB1.B8 USB2.4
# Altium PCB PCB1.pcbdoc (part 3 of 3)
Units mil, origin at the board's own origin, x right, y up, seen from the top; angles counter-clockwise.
Board outline 3855 x 3785 mil, 2 copper layers (Top Layer, Bottom Layer); 109 components, 98 nets, 407 pads, 573 vias.

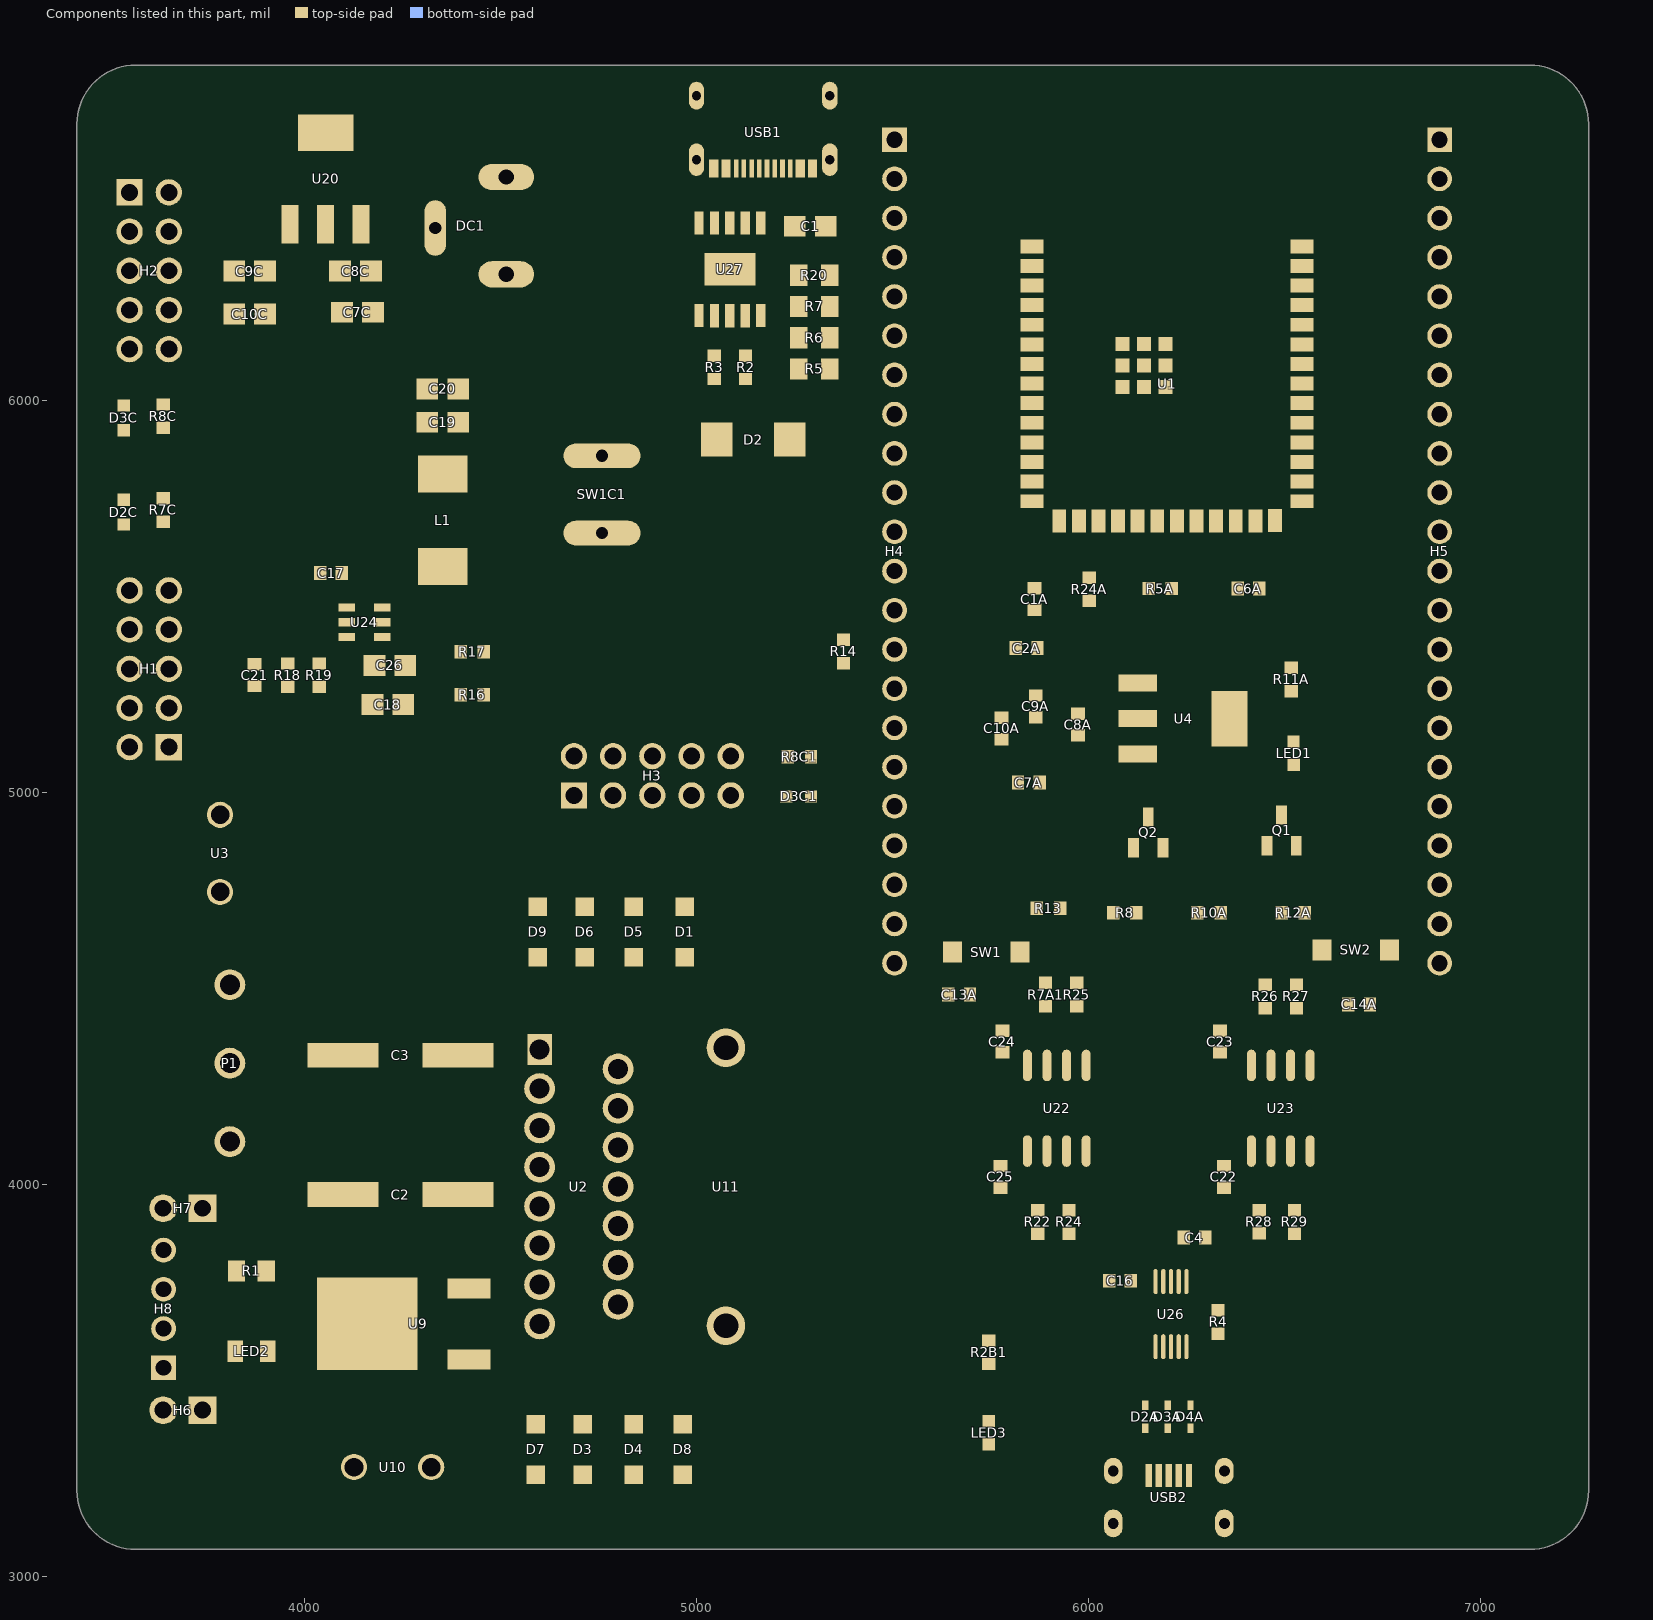
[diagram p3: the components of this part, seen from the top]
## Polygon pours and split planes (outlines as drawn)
VBUS2 on Top Layer (solid, remove dead copper, pour order 12): 5315.01,6389.27 5380.01,6389.27 5380.01,6029.27 5315.01,6029.27
VBUS2 on Bottom Layer (solid, remove dead copper, pour order 56): 5285.01,6574.27 5285.01,6504.27 5060.01,6504.27 5060.01,6574.27
$1N7262 on Top Layer (solid, remove dead copper, pour order 14): 5225.01,6378.65 5195.01,6414.27 5150.01,6414.27 5150.01,6484.27 5290.01,6484.27 5290.01,6024.27 5225.25,6024.27 5225.01,6024.03
3V3 on Top Layer (solid, remove dead copper, pour order 6): 4015.9,6399.65 4015.45,6514.24 3962.08,6514.24 3955.6,6735.02 4140.45,6735.02 4140.45,6524.2 4087.56,6524.2 4087.56,6377.31 3941.6,6299.19 3943.09,6110.02 3785.45,6035.02 3669.61,6035.02 3666.46,5967.33 3609.82,5966.66 3609.82,6575.02 3705.45,6575.02 3705.45,6110.02 3785.45,6110.02 3872.95,6152.92 3872.95,6360.02 3936,6363.83
VCC on Top Layer (solid, remove dead copper, pour order 22): 3620.79,5070.02 3620.79,5714.35 3691.78,5714.35 3725.45,5760.02 4145.55,6195.02 4300.12,6195.02 4300.12,6070.34 4300.45,6070.02 4170.45,6070.02 3790,5665 3765.63,5615.44 3704.37,5554.18 3704.37,5450.73 3710.45,5444.65 3710.45,5070.02
GND on Top Layer (solid, remove dead copper, pour order 26): 5254.96,5034.71 5254.96,4950.51 5255.45,4950.02 5248.28,4942.84 4637.34,4942.84 4637.34,5034.71
GND on Top Layer (solid, remove dead copper, pour order 4): 6057.82,6178.17 6222.58,6178.17 6222.58,6005.24 6057.82,6005.24
$1N5073 on Top Layer (solid, remove dead copper, pour order 16): 4173.66,5464.45 4173.66,5548.37 4232.01,5634.45 4423.03,5634.45 4423.03,5464.45
GND on Top Layer (solid, remove dead copper, pour order 8): 3590.45,5990.02 3575.45,5975.02 3504.37,5975.02 3504.37,6580.73 3592.58,6580.73 3590.45,6578.6
GND on Top Layer (solid, remove dead copper, pour order 10): 3586.35,5090.12 3571.35,5075.12 3510.27,5075.12 3510.27,5705.83 3586.35,5705.83
GND on Top Layer (solid, remove dead copper, pour order 54): 4866.11,4740 4866.11,4680.83 4685,4680.83 4685,4740
GND on Top Layer (solid, remove dead copper, pour order 46): 4186.17,4331.58 4186.17,4171.58 4032.77,4171.58 4032.77,4331.58
12V on Top Layer (solid, remove dead copper, pour order 48): 4482.74,3661.58 4482.74,3524.58 4357.74,3524.58 4357.74,3661.58
GND on Top Layer (solid, remove dead copper, pour order 50): 4642.77,3285.93 4642.77,3220.93 4562.77,3220.93 4562.77,3285.93
GND on Top Layer (solid, remove dead copper, pour order 56): 4998.17,3284.33 4998.17,3190.93 4927.77,3190.93 4927.77,3284.33
12V on Top Layer (solid, remove dead copper, pour order 52): 4863.18,3282.23 4863.18,3120.93 4682.78,3120.93 4682.78,3282.23
GND on Bottom Layer (solid, remove dead copper, pour order 64): 4209.57,4255.28 4209.57,4016.58 4052.77,4016.58 4052.77,4255.28
12V on Bottom Layer (solid, remove dead copper, pour order 66): 4477.73,3615.93 4477.73,3239.03 4383.13,3239.03 4383.13,3615.93
VCC on Top Layer (solid, remove dead copper, pour order 20): 4247.58,6190.02 4135.45,6190.02 4135.45,6260.02 4290.45,6260.02 4345.45,6205.02 4345.45,5930.84 4423.03,5879.45 4423.03,5759.45 4246.67,5759.45
GND on Top Layer (solid, remove dead copper, pour order 34): 3757.77,4161.58 3757.77,4361.58 3927.77,4361.58 3927.77,4261.58 4212.77,4261.58 4212.77,4161.58 3927.77,4161.58
12V on Top Layer (solid, remove dead copper, pour order 36): 3766.72,4391.58 3766.72,4549.48 4097.82,4549.48 4097.82,4516.58 4402.77,4516.58 4402.77,4396.58 4097.82,4396.58 4097.82,4391.58
GND on Top Layer (solid, remove dead copper, pour order 38): 4287.76,3794.08 4287.76,3509.38 4017.96,3509.38 4017.96,3794.08 4032.77,3794.08 4032.77,4081.58 4227.77,4081.58 4227.77,3794.08
12V on Top Layer (solid, remove dead copper, pour order 40): 4479.36,4241.58 4479.36,4142.28 4229.16,4142.28 4229.16,4241.58 4227.77,4241.58 4227.77,4406.58 4482.77,4406.58 4482.77,4241.58
12V on Top Layer (solid, remove dead copper, pour order 42): 4684.24,3201.53 4684.24,3120.93 4382.74,3120.93 4382.74,3201.53 4382.77,3201.53 4382.77,3255.93 4482.77,3255.93 4482.77,3201.53
12V on Bottom Layer (solid, remove dead copper, pour order 58): 4302.77,4501.58 4302.77,4376.58 4167.77,4376.58 4167.77,4611.58 4167.77,4641.58 4167.77,4751.58 4167.77,4841.58 4482.77,4841.58 4482.77,4751.58 4272.77,4751.58 4272.77,4651.58 5012.77,4651.58 5012.77,4501.58
12V on Bottom Layer (solid, remove dead copper, pour order 60): 4477.77,4231.58 4477.77,3606.58 4362.77,3606.58 4362.77,4139.88 4274.16,4139.88 4274.16,4231.58 4362.77,4231.58 4387.76,4231.58
12V on Bottom Layer (solid, remove dead copper, pour order 62): 5007.77,4651.58 5007.77,4146.38 4852.75,4146.38 4852.75,4146.58 4747.77,4146.58 4747.77,4236.58 4852.75,4236.58 4852.75,4651.58
GND1 on Top Layer (solid, remove dead copper, pour order 62): 5475,4185 7345,4185 7345,3010 5475,3010
GND on Bottom Layer (solid, remove dead copper, pour order 128): 5447.16,3025 3095,3025 3000,3120 3000,7090 7315,7090 7405,7000 7405,4290 7325,4210 5480,4210 5460,4190 5460,3060
VCC_3V3 on Top Layer (solid, remove dead copper, pour order 72): 6120,5215 6192.67,5220.09 6250.99,5278.41 6423.13,5280 6430,5273.13 6430,5099.4 6253.18,5099.4 6187.99,5164.6 6123.91,5164.6 6120,5168.51
GND1 on Bottom Layer (solid, remove dead copper, pour order 130): 5475,4185 7345,4185 7345,3010 5475,3010
12V on Top Layer (solid, remove dead copper, pour order 84): 4595,5055.02 4595,4850.93 5002.77,4850.93 5002.81,4678.63 4938.61,4678.63 4938.61,4750.93 4622.77,4750.93 4622.77,4678.53 4558.27,4678.53 4558.27,4750.93 4432.77,4750.93 4432.77,4850.93 4505,4850.93 4505,5085.02 4228.03,5085.02 4228.03,5419.45 4178.03,5419.45 4172.26,5425.22 4172.26,5454.45 4303,5454.45 4303,5294.45 4420.77,5294.45 4420.77,5205.02 4530.92,5205.02 4635.45,5305.48 4635.45,5693.56 4879.64,5693.56 4880.94,5434.56 4771.4,5299.22 4771.4,5140.96 4777.34,5135.02 5262.34,5135.02 5262.34,5065.02 5252.34,5055.02
VIN on Top Layer (solid, remove dead copper, pour order 86): 5110,5820.48 4895.45,5820.48 4895.45,5815.02 4630.45,5815.02 4630.45,6098.6 4420.45,6299.6 4420.45,6390.24 4608.26,6392.37 4608.69,6354.64 4895.45,6077.06 4895.45,5955 5110,5955
GND on Top Layer (solid, remove dead copper, pour order 92): 3285,3020 3285,7065 3345,7125 7480,7125 7425.21,7070.21 7425.21,4300.81 7319.4,4195 5505,4195 5490,4180 5490,3000 5470,3020
VCC on Top Layer (solid, remove dead copper, pour order 88): 4217.29,6192.73 4135.45,6192.73 4135.45,6372.61 4114.14,6380 4115,6395 4115,6505 4198.38,6505 4198.38,6383.36 4217.29,6367.11
VCC on Top Layer (solid, remove dead copper, pour order 90): 5355,5540 5390,5540 5390,5460 5355,5460

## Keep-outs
Top Layer:
  region: 7342.5,4146.25 5517.5,4146.25 5517.5,3033.75 5427.5,3033.75 5427.5,4236.25 7342.5,4236.25
Bottom Layer:
  region: 5797.58,6715.24 6592.58,6715.24 6592.58,6445.24 5797.58,6445.24
Board Outline Layer:
  region: 5632.58,6920.24 6797.58,6920.24 6797.58,6445.24 5632.58,6445.24
  region: 7340,4150 5515,4150 5515,3037.5 5425,3037.5 5425,4240 7340,4240
  lines w10: 3420,3220 ccw(c3570,3220) 3570,3070 7125,3070 ccw(c7125,3220) 7275,3220 7275,6705 ccw(c7125,6705) 7125,6855 3570,6855 ccw(c3570,6705) 3420,6705 3420,3220

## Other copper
Top Layer:
  drawing of 351 lines, arcs and shapes, not listed
Bottom Layer:
  region net GPIO4: 5547.7,6370.24 5548.06,6360.24 5545.84,6358.63 5540.73,6354.39 5526.01,6341.53 5525.66,6388.78 5540.55,6376.03 5545.61,6371.83
  region net GPIO5: 5547.7,6270.24 5548.06,6260.24 5545.84,6258.63 5540.73,6254.39 5526.01,6241.53 5525.66,6288.78 5540.55,6276.03 5545.61,6271.83
  region net GPIO6: 5547.7,6170.24 5548.06,6160.24 5545.84,6158.63 5540.73,6154.39 5526.01,6141.53 5525.66,6188.78 5540.55,6176.03 5545.61,6171.83
  region net GPIO7: 5543.66,6075.24 5551.52,6065.24 5550.88,6065.12 5550.07,6064.78 5547.99,6063.51 5545.41,6061.53 5542.46,6058.96 5539.26,6055.93 5535.94,6052.54 5532.63,6048.91 5529.47,6045.17 5521.62,6091.76 5523.55,6090.21 5525.8,6087.95 5531.09,6082.41 5534.05,6079.7 5537.16,6077.41 5538.76,6076.51 5540.38,6075.83 5542.01,6075.39
  region net GPIO15: 5551.21,5965.24 5544.07,5955.24 5542.42,5955.08 5540.78,5954.64 5539.16,5953.95 5537.56,5953.04 5534.44,5950.73 5531.48,5947.99 5526.19,5942.38 5523.94,5940.08 5522.02,5938.5 5529.17,5985.2 5532.4,5981.48 5535.75,5977.87 5539.1,5974.5 5542.31,5971.47 5545.26,5968.92 5547.81,5966.95 5549.84,5965.68 5550.62,5965.35
  region net GPIO16: 5547.7,5870.24 5548.06,5860.24 5545.84,5858.63 5540.73,5854.39 5526.01,5841.53 5525.66,5888.78 5540.55,5876.03 5545.61,5871.83
  region net GPIO17: 5547.7,5770.24 5548.06,5760.24 5545.84,5758.63 5540.73,5754.39 5526.01,5741.53 5525.66,5788.78 5540.55,5776.03 5545.61,5771.83
  region net GPIO18: 5547.7,5670.24 5548.06,5660.24 5545.84,5658.63 5540.73,5654.39 5526.01,5641.53 5525.66,5688.78 5540.55,5676.03 5545.61,5671.83
  region net GPIO8: 5547.7,5570.24 5548.06,5560.24 5545.84,5558.63 5540.73,5554.39 5526.01,5541.53 5525.66,5588.78 5540.55,5576.03 5545.61,5571.83
  region net GPIO3: 5547.7,5470.24 5548.06,5460.24 5545.84,5458.63 5540.73,5454.39 5526.01,5441.53 5525.66,5488.78 5540.55,5476.03 5545.61,5471.83
  region net GPIO46: 5547.7,5370.24 5548.06,5360.24 5545.84,5358.63 5540.73,5354.39 5526.01,5341.53 5525.66,5388.78 5540.55,5376.03 5545.61,5371.83
  region net GPIO9: 5547.7,5270.24 5548.06,5260.24 5545.84,5258.63 5540.73,5254.39 5526.01,5241.53 5525.66,5288.78 5540.55,5276.03 5545.61,5271.83
  region net GPIO10: 5548.94,5194.26 5539.7,5170.88 5538.61,5169.64 5537.66,5168.27 5536.15,5165.24 5535.05,5161.96 5534.24,5158.6 5532.99,5152.37 5532.33,5149.84 5531.47,5147.93 5518.63,5193.4 5520.55,5192.56 5522.57,5191.85 5526.83,5190.78 5531.22,5190.2 5535.56,5190.08 5539.68,5190.44 5543.41,5191.26 5545.06,5191.84 5546.55,5192.53 5547.85,5193.34
  region net GPIO11: 5547.7,5070.24 5548.06,5060.24 5545.84,5058.63 5540.73,5054.39 5526.01,5041.53 5525.66,5088.78 5540.55,5076.03 5545.61,5071.83
  region net GPIO12: 5547.7,4970.24 5548.06,4960.24 5545.84,4958.63 5540.73,4954.39 5526.01,4941.53 5525.66,4988.78 5540.55,4976.03 5545.61,4971.83
  region net GPIO13: 5547.7,4870.24 5548.06,4860.24 5545.84,4858.63 5540.73,4854.39 5526.01,4841.53 5525.66,4888.78 5540.55,4876.03 5545.61,4871.83
  region net GPIO14: 5547.7,4770.24 5548.06,4760.24 5545.84,4758.63 5540.73,4754.39 5526.01,4741.53 5525.66,4788.78 5540.55,4776.03 5545.61,4771.83
  region net GPIO1: 6843.38,6375 6865.88,6385 6867.53,6385.11 6869.17,6385.41 6870.78,6385.89 6872.38,6386.52 6875.48,6388.09 6878.42,6389.93 6883.71,6393.56 6885.97,6394.92 6887.93,6395.69 6865.43,6354.15 6863.68,6358.04 6861.39,6361.81 6858.67,6365.33 6855.67,6368.48 6852.52,6371.15 6849.33,6373.21 6847.76,6373.97 6846.24,6374.53 6844.78,6374.88
  region net GPIO2: 6851.94,6260.24 6852.3,6270.24 6854.39,6271.83 6859.45,6276.03 6874.34,6288.78 6873.99,6241.53 6859.27,6254.39 6854.16,6258.63
  region net GPIO42: 6851.94,6160.24 6852.3,6170.24 6854.39,6171.83 6859.45,6176.03 6874.34,6188.78 6873.99,6141.53 6859.27,6154.39 6854.16,6158.63
  region net GPIO41: 6850.15,6062.74 6854.25,6072.74 6855.9,6072.9 6857.54,6073.35 6859.17,6074.07 6860.78,6075.02 6863.9,6077.42 6866.88,6080.28 6872.18,6086.18 6874.41,6088.62 6876.3,6090.34 6872.19,6043.28 6865.09,6050.42 6858.35,6056.65 6853.03,6061.06 6851.22,6062.3
  region net GPIO40: 6851.94,5960.24 6852.3,5970.24 6854.39,5971.83 6859.45,5976.03 6874.34,5988.78 6873.99,5941.53 6859.27,5954.39 6854.16,5958.63
  region net GPIO39: 6851.94,5860.24 6852.3,5870.24 6854.39,5871.83 6859.45,5876.03 6874.34,5888.78 6873.99,5841.53 6859.27,5854.39 6854.16,5858.63
  region net GPIO38: 6851.94,5760.24 6852.3,5770.24 6854.39,5771.83 6859.45,5776.03 6874.34,5788.78 6873.99,5741.53 6859.27,5754.39 6854.16,5758.63
  region net GPIO37: 6851.94,5660.24 6852.3,5670.24 6854.39,5671.83 6859.45,5676.03 6874.34,5688.78 6873.99,5641.53 6859.27,5654.39 6854.16,5658.63
  region net GPIO36: 6860.33,5570.42 6850.76,5594.13 6851.87,5593.19 6853.18,5592.37 6854.68,5591.66 6856.35,5591.07 6860.08,5590.23 6864.21,5589.87 6868.54,5589.99 6872.91,5590.58 6877.14,5591.67 6879.15,5592.39 6881.05,5593.24 6868.72,5547.63 6867.85,5549.52 6867.16,5552.03 6865.86,5558.21 6865.02,5561.54 6863.89,5564.8 6862.37,5567.81 6861.42,5569.18
  region net GPIO35: 6863.37,5502.38 6880.05,5499.84 6881.32,5498.77 6882.75,5497.89 6884.33,5497.19 6886.03,5496.63 6889.68,5495.9 6893.47,5495.54 6900.68,5495.26 6903.65,5495.04 6905.93,5494.54 6864.33,5472.16 6865.21,5476.73 6865.8,5481.43 6866.1,5486.07 6866.1,5490.5 6865.83,5494.52 6865.28,5497.95 6864.46,5500.63 6863.95,5501.63
  region net GPIO0: 6851.94,5360.24 6852.3,5370.24 6854.39,5371.83 6859.45,5376.03 6874.34,5388.78 6873.99,5341.53 6859.27,5354.39 6854.16,5358.63
  region net GPIO45: 6851.94,5260.24 6852.3,5270.24 6854.39,5271.83 6859.45,5276.03 6874.34,5288.78 6873.99,5241.53 6859.27,5254.39 6854.16,5258.63
  region net GPIO48: 6851.94,5160.24 6852.3,5170.24 6854.39,5171.83 6859.45,5176.03 6874.34,5188.78 6873.99,5141.53 6859.27,5154.39 6854.16,5158.63
  region net GPIO47: 6851.94,5060.24 6852.3,5070.24 6854.39,5071.83 6859.45,5076.03 6874.34,5088.78 6873.99,5041.53 6859.27,5054.39 6854.16,5058.63
  region net GPIO21: 6851.94,4960.24 6852.3,4970.24 6854.39,4971.83 6859.45,4976.03 6874.34,4988.78 6873.99,4941.53 6859.27,4954.39 6854.16,4958.63
  region net GPIO20: 6868.21,4831.14 6861.14,4838.21 6861.54,4840.87 6862.15,4847.45 6863.57,4866.97 6896.97,4833.57 6877.45,4832.15 6870.87,4831.54
  region net GPIO19: 6852.12,4760 6852.12,4770 6854.28,4771.6 6859.36,4775.82 6874.17,4788.62 6874.17,4741.38 6859.36,4754.18 6854.28,4758.4
  region net EB: 3678.24,3384.6 3651.88,3382.68 3650.49,3383.92 3648.97,3385.02 3647.35,3385.99 3645.64,3386.85 3642.06,3388.25 3638.39,3389.33 3631.51,3390.89 3628.65,3391.56 3626.4,3392.28 3674.16,3415.59 3673.3,3411.44 3672.88,3407 3672.87,3402.45 3673.26,3397.99 3674.01,3393.8 3675.11,3390.04 3676.53,3386.92 3677.35,3385.65
  region net IN1: 3607.77,3821.58 3607.77,3841.58 3608.59,3841.71 3609.4,3842.09 3610.2,3842.67 3610.99,3843.44 3612.51,3845.4 3613.96,3847.72 3616.6,3852.48 3617.75,3854.43 3618.77,3855.76 3621.4,3808.59 3620.19,3809.81 3618.79,3811.6 3615.52,3815.96 3613.7,3818.08 3611.78,3819.88 3610.8,3820.58 3609.8,3821.12 3608.79,3821.46
  region net $1N5190: 4216.43,5384.45 4216.43,5374.45 4214.66,5374.24 4212.71,5373.7 4210.89,5372.94 4209.54,5372.07 4209.54,5386.83 4210.89,5385.96 4212.71,5385.19 4214.66,5384.65
  region net $1N5190: 4344.36,5364.05 4351.44,5371.12 4352.83,5370.01 4354.6,5369.01 4356.42,5368.27 4357.99,5367.93 4347.55,5357.49 4347.22,5359.07 4346.47,5360.89 4345.47,5362.65
  region net GPIO1: 6483.93,6425.24 6483.93,6415.24 6482.12,6414.89 6479.85,6413.98 6477.52,6412.7 6475.52,6411.23 6475.52,6429.24 6477.52,6427.77 6479.85,6426.49 6482.12,6425.58
  region net GPIO2: 6483.93,6370.24 6483.93,6360.24 6482.12,6359.89 6479.85,6358.98 6477.52,6357.7 6475.52,6356.23 6475.52,6374.24 6477.52,6372.77 6479.85,6371.49 6482.12,6370.58
  region net U0TXD: 6414.56,6290.14 6407.49,6297.21 6408.52,6298.73 6409.48,6300.98 6410.22,6303.53 6410.6,6305.99 6423.33,6293.25 6420.88,6292.88 6418.32,6292.14 6416.08,6291.18
  region net U0RXD: 6331.23,6250.24 6331.23,6260.24 6333.04,6260.58 6335.31,6261.49 6337.64,6262.77 6339.64,6264.24 6339.64,6246.23 6337.64,6247.7 6335.31,6248.98 6333.04,6249.89
  region net GPIO42: 6483.93,6210.24 6483.93,6200.24 6482.12,6199.89 6479.85,6198.98 6477.52,6197.7 6475.52,6196.23 6475.52,6214.24 6477.52,6212.77 6479.85,6211.49 6482.12,6210.58
  region net GPIO41: 6483.93,6160.24 6483.93,6150.24 6482.12,6149.89 6479.85,6148.98 6477.52,6147.7 6475.52,6146.23 6475.52,6164.24 6477.52,6162.77 6479.85,6161.49 6482.12,6160.58
  region net GPIO40: 6483.93,6100.24 6483.93,6090.24 6482.12,6089.89 6479.85,6088.98 6477.52,6087.7 6475.52,6086.23 6475.52,6104.24 6477.52,6102.77 6479.85,6101.49 6482.12,6100.58
  region net GPIO39: 6483.93,6050.24 6483.93,6040.24 6482.12,6039.89 6479.85,6038.98 6477.52,6037.7 6475.52,6036.23 6475.52,6054.24 6477.52,6052.77 6479.85,6051.49 6482.12,6050.58
  region net GPIO38: 6485.82,5998 6485.82,5988 6484.01,5987.65 6481.74,5986.75 6479.41,5985.46 6477.42,5984 6477.42,6002 6479.41,6000.53 6481.74,5999.25 6484.01,5998.34
  region net GPIO37: 6468.93,5955.24 6468.93,5945.24 6467.12,5944.89 6464.85,5943.98 6462.52,5942.7 6460.52,5941.23 6460.52,5959.24 6462.52,5957.77 6464.85,5956.49 6467.12,5955.58
  region net GPIO36: 6449.88,5926.18 6449.88,5916.18 6448.07,5915.84 6445.8,5914.93 6443.47,5913.65 6441.47,5912.18 6441.47,5930.19 6443.47,5928.72 6445.8,5927.43 6448.07,5926.53
  region net GPIO35: 6413.93,5895.24 6413.93,5885.24 6412.12,5884.89 6409.85,5883.98 6407.52,5882.7 6405.52,5881.23 6405.52,5899.24 6407.52,5897.77 6409.85,5896.49 6412.12,5895.58
  region net GPIO48: 6441.48,5766.01 6431.48,5766.69 6431.15,5768.45 6430.27,5770.7 6429.04,5773.05 6427.63,5775.1 6445.63,5774.41 6444.1,5772.46 6442.77,5770.15 6441.83,5767.87
  region net GPIO47: 6405.57,5806.9 6395.57,5794.87 6395.48,5796.38 6395.23,5797.85 6394.83,5799.25 6394.31,5800.51 6393.69,5801.6 6393.01,5802.45 6392.28,5803.03 6391.52,5803.27 6404.59,5815.3 6404.75,5813.75 6405.08,5811.73 6405.42,5809.39
  region net GPIO21: 6373.66,5793.81 6366.59,5786.74 6365.07,5787.77 6362.82,5788.73 6360.27,5789.47 6357.81,5789.85 6370.55,5802.58 6370.92,5800.13 6371.66,5797.58 6372.62,5795.33
  region net GPIO45: 6479.83,5766.14 6479.83,5756.14 6478.02,5755.79 6475.76,5754.89 6473.43,5753.6 6471.43,5752.13 6471.43,5770.14 6473.43,5768.67 6475.76,5767.39 6478.02,5766.48
  region net GPIO0: 6413.93,5855.24 6413.93,5845.24 6412.12,5844.89 6409.85,5843.98 6407.52,5842.7 6405.52,5841.23 6405.52,5859.24 6407.52,5857.77 6409.85,5856.49 6412.12,5855.58
  region net GPIO4: 5911.23,6290.24 5911.23,6300.24 5913.04,6300.58 5915.31,6301.49 5917.64,6302.77 5919.64,6304.24 5919.64,6286.23 5917.64,6287.7 5915.31,6288.98 5913.04,6289.89
  region net GPIO5: 5915.7,6240.24 5908.2,6250.24 5909.42,6250.34 5910.68,6250.65 5911.95,6251.14 5913.17,6251.76 5914.3,6252.5 5915.28,6253.32 5916.06,6254.21 5916.61,6255.12 5924.11,6238.74 5919.63,6239.77 5917.4,6240.11
  region net GPIO6: 5908.2,6200.24 5915.7,6210.24 5917.4,6210.36 5919.63,6210.7 5924.11,6211.73 5916.61,6195.35 5916.06,6196.26 5915.28,6197.15 5914.3,6197.97 5913.17,6198.71 5911.95,6199.33 5910.68,6199.82 5909.42,6200.13
  region net GPIO7: 5907.86,6155.24 5915.7,6165.24 5917.4,6165.36 5919.63,6165.7 5924.11,6166.73 5916.26,6151.23 5915.84,6151.98 5915.14,6152.7 5914.21,6153.38 5913.1,6153.98 5910.54,6154.89 5909.19,6155.15
  region net GPIO15: 5913.28,6092.74 5909.53,6102.74 5910.53,6102.84 5911.65,6103.14 5914.02,6104.19 5916.24,6105.68 5917.18,6106.52 5917.94,6107.39 5921.69,6089.77 5919.49,6090.86 5917.09,6091.81 5914.89,6092.48
  region net GPIO16: 5911.23,6035.24 5911.23,6045.24 5913.04,6045.58 5915.31,6046.49 5917.64,6047.77 5919.64,6049.24 5919.64,6031.23 5917.64,6032.7 5915.31,6033.98 5913.04,6034.89
  region net GPIO17: 5911.23,5980.24 5911.23,5990.24 5913.04,5990.58 5915.31,5991.49 5917.64,5992.77 5919.64,5994.24 5919.64,5976.23 5917.64,5977.7 5915.31,5978.98 5913.04,5979.89
  region net GPIO18: 5915.7,5915.24 5908.2,5925.24 5909.42,5925.34 5910.68,5925.65 5911.95,5926.14 5913.17,5926.76 5914.3,5927.5 5915.28,5928.32 5916.06,5929.21 5916.61,5930.12 5924.11,5913.74 5919.63,5914.77 5917.4,5915.11
  region net GPIO8: 5927.58,5855.86 5917.58,5863.36 5917.45,5865.05 5917.11,5867.28 5916.09,5871.76 5932.46,5864.26 5931.55,5863.72 5930.67,5862.93 5929.85,5861.95 5929.11,5860.82 5928.48,5859.6 5928,5858.33 5927.69,5857.07
  region net GPIO3: 5824.56,5625.14 5817.49,5632.21 5818.52,5633.73 5819.48,5635.98 5820.22,5638.53 5820.6,5640.99 5833.33,5628.25 5830.88,5627.88 5828.32,5627.14 5826.08,5626.18
  region net GPIO46: 5871.17,5623.52 5864.1,5630.59 5865.14,5632.12 5866.1,5634.36 5866.84,5636.92 5867.21,5639.37 5879.95,5626.63 5877.5,5626.26 5874.94,5625.52 5872.7,5624.56
  region net GPIO9: 5904.56,5580.14 5897.49,5587.21 5898.52,5588.73 5899.48,5590.98 5900.22,5593.53 5900.6,5595.99 5913.33,5583.25 5910.88,5582.88 5908.32,5582.14 5906.08,5581.18
  region net GPIO19: 6317.54,5851.88 6307.54,5851.88 6307.19,5853.69 6306.28,5855.95 6305,5858.29 6303.53,5860.28 6321.54,5860.28 6320.07,5858.29 6318.79,5855.95 6317.88,5853.69
  region net GPIO20: 6335.09,5835.68 6328.02,5842.75 6328.86,5844.07 6329.65,5846.15 6330.27,5848.58 6330.6,5850.99 6343.33,5838.25 6340.92,5837.92 6338.49,5837.3 6336.42,5836.51
  region net GPIO0: 6212.58,5878.89 6202.58,5878.89 6202.24,5880.7 6201.33,5882.96 6200.05,5885.29 6198.58,5887.29 6216.59,5887.29 6215.12,5885.29 6213.83,5882.96 6212.93,5880.7
  region net GPIO10: 5943.57,5574.75 5936.5,5581.82 5937.54,5583.35 5938.5,5585.59 5939.24,5588.14 5939.61,5590.6 5952.35,5577.86 5949.89,5577.49 5947.34,5576.75 5945.1,5575.79
  region net GPIO11: 6083.42,5741.97 6076.35,5734.9 6074.82,5735.93 6072.58,5736.89 6070.02,5737.63 6067.57,5738.01 6080.31,5750.74 6080.68,5748.29 6081.42,5745.73 6082.38,5743.49
  region net GPIO12: 6120.24,5751.88 6110.24,5751.88 6109.89,5753.69 6108.99,5755.95 6107.7,5758.29 6106.23,5760.28 6124.24,5760.28 6122.77,5758.29 6121.49,5755.95 6120.58,5753.69
  region net GPIO13: 6179.25,5761.88 6169.25,5761.88 6168.91,5763.69 6168,5765.95 6166.72,5768.29 6165.25,5770.28 6183.26,5770.28 6181.79,5768.29 6180.51,5765.95 6179.6,5763.69
  region net GPIO14: 6185.57,5613.89 6175.57,5613.89 6175.23,5615.7 6174.32,5617.96 6173.04,5620.29 6171.57,5622.29 6189.58,5622.29 6188.11,5620.29 6186.82,5617.96 6185.92,5615.7
  region net GPIO0: 5870.61,4815.33 5877.68,4808.26 5876.64,4806.74 5875.68,4804.49 5874.94,4801.94 5874.57,4799.48 5861.83,4812.22 5864.28,4812.59 5866.84,4813.33 5869.08,4814.3
  region net CHIP_PU: 6032.58,6319.87 6022.58,6334.93 6022.71,6336.19 6023.05,6337.42 6024.11,6339.74 6025.25,6341.76 6025.98,6343.34 6036.51,6328.28 6035.78,6328.14 6035.07,6327.65 6034.4,6326.85 6033.81,6325.78 6033.31,6324.5 6032.92,6323.06 6032.67,6321.5
  region net CHIP_PU: 6070.61,4775.33 6077.68,4768.26 6076.64,4766.74 6075.68,4764.49 6074.94,4761.94 6074.57,4759.48 6061.83,4772.22 6064.28,4772.59 6066.84,4773.33 6069.08,4774.3
  region net DTR: 6262.68,4852.21 6255.61,4845.14 6254.08,4846.18 6251.84,4847.14 6249.28,4847.88 6246.83,4848.25 6259.57,4860.99 6259.94,4858.53 6260.68,4855.98 6261.64,4853.73
  region net DTR: 6272.58,4826.58 6282.58,4826.58 6282.93,4824.77 6283.83,4822.51 6285.12,4820.18 6286.59,4818.18 6268.58,4818.18 6270.05,4820.18 6271.33,4822.51 6272.24,4824.77
  region net CHIP_PU: 6244.59,5556.7 6234.59,5556.7 6234.24,5558.5 6233.34,5560.77 6232.05,5563.1 6230.58,5565.1 6248.59,5565.1 6247.12,5563.1 6245.84,5560.77 6244.93,5558.5
  region net CHIP_PU: 6229.59,5584.92 6239.59,5592.42 6239.7,5591.21 6240.01,5589.94 6240.49,5588.68 6241.11,5587.46 6241.85,5586.33 6242.68,5585.35 6243.56,5584.56 6244.47,5584.01 6228.09,5576.51 6229.12,5581 6229.46,5583.23
  region net $1N7060: 5010.32,6129.24 5014.57,6125 5014.1,6123.81 5013.61,6121.4 5013.18,6118.24 5012.87,6114.82 5000.14,6127.55 5003.56,6127.85 5006.72,6128.29 5009.13,6128.78
  region net $1N7060: 5109.71,6161.27 5106.62,6167.27 5107.32,6167.42 5108.22,6167.83 5110.42,6169.32 5112.82,6171.42 5115.02,6173.83 5118.11,6156.1 5116.56,6157.34 5114.54,6159.07 5113.4,6159.91 5112.2,6160.61 5110.96,6161.09
  region net CHIP_PU: 6674.81,4584.91 6667.74,4591.98 6668.77,4593.51 6669.73,4595.75 6670.48,4598.3 6670.85,4600.75 6683.58,4588.02 6681.13,4587.65 6678.57,4586.91 6676.33,4585.95
  region net USB_DN: 6202.1,3518.3 6190.82,3518.33 6191.56,3519.25 6192.17,3520.39 6192.64,3521.68 6192.97,3523.07 6193.14,3524.5 6193.15,3525.91 6192.97,3527.24 6192.61,3528.42 6209.66,3522.63
  region net USB_DN: 6169.15,3432.12 6177.15,3432.12 6177.58,3430.63 6178.71,3428.47 6180.31,3426.04 6182.15,3423.72 6164.15,3423.72 6165.98,3426.04 6167.59,3428.47 6168.72,3430.63
  region net $3N11016: 5975.7,3707.39 5975.7,3715.39 5977.19,3715.82 5979.35,3716.96 5981.78,3718.56 5984.1,3720.39 5984.1,3702.39 5981.78,3704.23 5979.35,3705.83 5977.19,3706.96
  region net $3N11016: 5947.56,3803.44 5939.56,3797.14 5939.43,3798.19 5939.05,3799.34 5938.48,3800.54 5937.73,3801.74 5935.85,3803.94 5934.8,3804.84 5933.7,3805.54 5950.57,3811.84
  region net U0TXD: 6001.34,4585 6001.34,4575 5999.53,4574.66 5997.26,4573.75 5994.93,4572.47 5992.94,4571 5992.94,4589 5994.93,4587.53 5997.26,4586.25 5999.53,4585.34
  region net U0RXD: 5961.34,4620 5961.34,4610 5959.53,4609.66 5957.26,4608.75 5954.93,4607.47 5952.94,4606 5952.94,4624 5954.93,4622.53 5957.26,4621.25 5959.53,4620.34
  region net CHIP_PU: 6146.35,4510 6146.35,4500 6144.54,4499.66 6142.27,4498.75 6139.94,4497.47 6137.94,4495.99 6137.94,4514.01 6139.94,4512.53 6142.27,4511.25 6144.54,4510.34
  region net CC1: 5195.58,6505.6 5191.34,6509.84 5191.8,6511.03 5192.29,6513.44 5192.73,6516.6 5193.04,6520.02 5205.77,6507.29 5202.34,6506.99 5199.19,6506.55 5196.78,6506.06
  region net USBD-: 5155.58,6510.6 5151.34,6514.84 5151.8,6516.03 5152.29,6518.44 5152.73,6521.6 5153.04,6525.02 5165.77,6512.29 5162.34,6511.99 5159.19,6511.55 5156.78,6511.06
  region net USBD-: 5031.35,6497.27 5031.35,6491.27 5030.18,6490.75 5028.13,6489.4 5025.59,6487.47 5022.95,6485.27 5022.95,6503.27 5025.59,6501.07 5028.13,6499.15 5030.18,6497.79
  region net CC1: 5037.01,6181.14 5043.01,6188.64 5043.17,6187.57 5043.61,6186.41 5044.28,6185.21 5045.16,6184.01 5046.2,6182.86 5047.36,6181.82 5048.61,6180.93 5049.89,6180.24 5033.53,6172.74 5034.29,6174.31 5035.47,6176.33 5036.54,6178.65 5036.89,6179.88
  region net VCC: 4283.64,5831.95 4286.14,5856.95 4290.26,5857.25 4291.97,5857.57 4293.03,5857.93 4290.53,5843.08 4290.2,5843.28 4289.86,5843.17 4289.13,5842.18 4288.33,5840.43 4287.48,5838.26 4286.59,5836 4285.64,5833.97 4284.66,5832.51 4284.15,5832.1
  region net IN2: 3647.18,4251.58 3647.18,4231.58 3645.02,4231.49 3642.91,4231.27 3638.9,4230.58 3635.44,4229.89 3632.77,4229.57 3632.77,4253.59 3635.44,4253.27 3638.9,4252.58 3642.91,4251.89 3645.02,4251.67
  region net EA: 3772.18,4041.58 3772.18,4021.58 3770.02,4021.49 3767.91,4021.27 3763.9,4020.58 3760.44,4019.89 3757.77,4019.57 3757.77,4043.59 3760.44,4043.27 3763.9,4042.58 3767.91,4041.89 3770.02,4041.67
  region net IN3: 3717.18,3646.58 3717.18,3626.58 3715.02,3626.49 3712.91,3626.27 3708.9,3625.58 3705.44,3624.89 3702.77,3624.57 3702.77,3648.59 3705.44,3648.27 3708.9,3647.58 3712.91,3646.89 3715.02,3646.67
  region net EA: 3962.77,3570.33 3982.77,3570.33 3982.86,3568.18 3983.08,3566.06 3983.77,3562.06 3984.46,3558.6 3984.77,3555.93 3960.77,3555.93 3961.08,3558.6 3961.77,3562.06 3962.46,3566.06 3962.68,3568.18
  region net IN4: 3717.18,3536.58 3717.18,3516.58 3715.02,3516.49 3712.91,3516.27 3708.9,3515.58 3705.44,3514.89 3702.77,3514.57 3702.77,3538.59 3705.44,3538.27 3708.9,3537.58 3712.91,3536.89 3715.02,3536.67
  region net EA: 4514.13,3495.93 4514.13,3475.93 4511.98,3475.84 4509.86,3475.62 4505.86,3474.93 4502.4,3474.24 4499.73,3473.93 4499.73,3497.93 4502.4,3497.62 4505.86,3496.93 4509.86,3496.24 4511.98,3496.02
  region net EB: 3768.37,3350.93 3768.37,3370.93 3770.52,3371.02 3772.64,3371.24 3776.64,3371.93 3780.1,3372.62 3782.77,3372.93 3782.77,3348.93 3780.1,3349.24 3776.64,3349.93 3772.64,3350.62 3770.52,3350.84
  region net VBUS: 6017.5,3602.5 ccw(c6017.5,3727.5) 6092.5,3627.5 6105,3590
  region net IN4: 4864.64,3785.93 4836.04,3765.93 4833.97,3765.84 4831.92,3765.58 4827.88,3764.64 4823.97,3763.29 4820.26,3761.71 4813.63,3758.55 4810.84,3757.32 4808.48,3756.55 4837.08,3808.22 4837.94,3806.13 4839.01,3804.06 4840.26,3802.02 4841.69,3800.03 4843.26,3798.11 4844.96,3796.27 4848.68,3792.9 4852.66,3790.04 4854.71,3788.85 4856.76,3787.85 4858.8,3787.03 4860.81,3786.43 4862.76,3786.06
  region net IN3: 4761.69,3851.36 4754.16,3872.11 4756.64,3882.13 4761.59,3903.65 4796.22,3855.81 4790.94,3856.15 4785.54,3856.17 4780.2,3855.92 4775.14,3855.41 4770.56,3854.68 4766.66,3853.74 4763.63,3852.63 4762.52,3852.01
  region net GND: 4859.31,4004.08 4846.68,3969.08 4844.05,3968.89 4840.86,3968.35 4837.28,3967.51 4833.47,3966.43 4829.58,3965.14 4825.79,3963.71 4822.25,3962.17 4819.12,3960.59 4831.75,4018.27 4834.08,4015.63 4837.05,4013.06 4840.5,4010.66 4844.27,4008.52 4848.19,4006.7 4852.12,4005.3 4855.88,4004.4
  region net IN2: 4553.81,4061.39 4556.22,4087.27 4557.27,4086.4 4558.59,4085.61 4560.15,4084.88 4561.94,4084.23 4566.08,4083.17 4570.8,4082.45 4575.89,4082.09 4581.14,4082.12 4586.35,4082.54 4591.32,4083.4 4562.98,4031.59 4562.3,4034.23 4561.75,4037.62 4560.53,4045.77 4559.58,4050.08 4558.24,4054.27 4557.37,4056.25 4556.36,4058.12 4555.18,4059.84
  region net EA: 4749.59,4080.93 4743.49,4100.93 4744.39,4101.05 4745.49,4101.4 4748.23,4102.71 4751.54,4104.76 4755.27,4107.41 4759.24,4110.55 4763.3,4114.06 4767.29,4117.81 4771.05,4121.68 4777.15,4062.94 4767.68,4069.54 4759.07,4075.31 4752.61,4079.38 4750.59,4080.53
  region net IN1: 4553.81,4161.39 4556.22,4187.27 4557.27,4186.4 4558.59,4185.61 4560.15,4184.88 4561.94,4184.23 4566.08,4183.17 4570.8,4182.45 4575.89,4182.09 4581.14,4182.12 4586.35,4182.54 4591.32,4183.4 4562.98,4131.59 4562.3,4134.23 4561.75,4137.62 4560.53,4145.77 4559.58,4150.08 4558.24,4154.27 4557.37,4156.25 4556.36,4158.12 4555.18,4159.84

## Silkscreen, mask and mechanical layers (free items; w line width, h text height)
Top Silkscreen Layer:
  drawing of 9 lines, arcs and shapes, not listed
  text "3V3" at 5576.58,6700.24 h30 r270
  text "GND" at 6780,6700 h30 r270
  text "3V3" at 5576.58,6600.24 h30 r270
  text "TX" at 6782.5,6591 h30 r270
  text "RST" at 5576.58,6495.24 h30 r270
  text "RX" at 6785,6490 h30 r270
  text "GND" at 3450.45,6420.02 h45 r270
  text "4" at 5576.58,6375.24 h30 r270
  text "1" at 6787.58,6370.24 h30 r270
  text "5" at 5576.58,6275.24 h30 r270
  text "2" at 6787.58,6271.62 h30 r270
  text "42" at 6787.58,6190.24 h30 r270
  text "6" at 5576.58,6175.24 h30 r270
  text "3.3V" at 3745,6115 h45 r270
  text "41" at 6787.58,6085.24 h30 r270
  text "7" at 5576.58,6075.24 h30 r270
  text "15" at 5576.58,5990.24 h30 r270
  text "40" at 6787.58,5990.24 h30 r270
  text "16" at 5576.58,5890.24 h30 r270
  text "39" at 6787.58,5890.24 h30 r270
  text "38" at 6787.58,5790.24 h30 r270
  text "17" at 5576.58,5785.24 h30 r270
  text "37" at 6787.58,5689.96 h30 r270
  text "18" at 5576.58,5685.24 h30 r270
  text "36" at 6787.58,5586.35 h30 r270
  text "8" at 5576.58,5580.24 h30 r270
  text "35" at 6787.58,5482.74 h30 r270
  text "3" at 5576.58,5480.24 h30 r270
  text "GND" at 3440.45,5395.02 h45 r270
  text "46" at 5576.58,5395.24 h30 r270
  text "0" at 6787.58,5379.12 h30 r270
  text "5V" at 3745,5330 h45 r270
  text "45" at 6787.58,5290.24 h30 r270
  text "9" at 5576.58,5280.24 h30 r270
  text "10" at 5576.58,5190.24 h30 r270
  text "48" at 6787.58,5190.24 h30 r270
  text "12V" at 4842.32,5168.56 h45
  text "47" at 6787.58,5090.24 h30 r270
  text "11" at 5576.58,5085.24 h30 r270
  text "OUT1" at 3512.5,5006.1 h45 r270
  text "12" at 5576.58,4990.24 h30 r270
  text "21" at 6787.58,4985.24 h30 r270
  text "13" at 5576.58,4890.24 h30 r270
  text "20" at 6787.58,4885.24 h30 r270
  text "GND" at 4964.98,4865.45 h45
  text "OUT2" at 3507.5,4806.1 h45 r270
  text "19" at 6787.58,4790.24 h30 r270
  text "14" at 5576.58,4786.24 h30 r270
  text "清华大学第29届硬件设计大赛" at 7205,4750 h120 r90
  text "GND" at 6787.58,4710.24 h30 r270
  text "5V" at 5576.58,4690.24 h30 r270
  text "RESET" at 6625,4675 h45
  text "BOOT" at 5690,4650 h45
  text "GND" at 5576.58,4605.24 h30 r270
  text "GND" at 6787.58,4590.24 h30 r270
  text "12V" at 3530.93,4549.74 h45 r270
  text "GND" at 3525.93,4334.74 h45 r270
  text "5V" at 3527.77,4141.58 h45 r270
  text "EA" at 3525.64,3965.35 h45 r270
  text "IN1" at 3527.77,3866.58 h45 r270
  text "IN2" at 3525.93,3759.74 h45 r270
  text "IN3" at 3530,3665 h45 r270
  text "IN4" at 3525.93,3554.74 h45 r270
  text "EB" at 3525,3435 h45 r270
  text "5V" at 3684.65,3317.5 h45
  text "OUT4" at 3942.5,3206.1 h45 r270
  text "OUT3" at 4510,3105 h45 r90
